VERSION 5.8 ;
BUSBITCHARS "[]" ;
DIVIDERCHAR "/" ;
UNITS
    DATABASE MICRONS 1000 ;
END UNITS

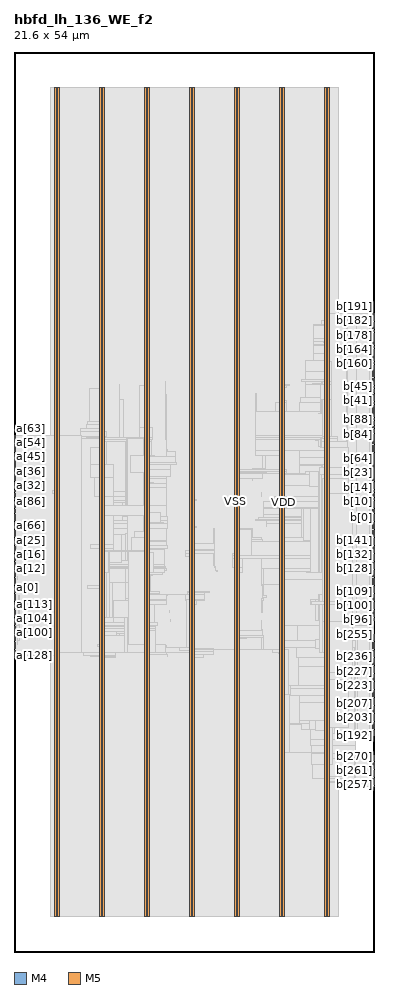
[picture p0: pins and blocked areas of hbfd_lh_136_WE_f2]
MACRO hbfd_lh_136_WE_f2
  FOREIGN hbfd_lh_136_WE_f2 0 0 ;
  CLASS BLOCK ;
  SIZE 21.6 BY 54 ;
  PIN a[0]
    DIRECTION INPUT ;
    USE SIGNAL ;
    PORT
      LAYER M4 ;
        RECT  0 21.84 0.084 21.864 ;
    END
  END a[0]
  PIN a[100]
    DIRECTION INPUT ;
    USE SIGNAL ;
    PORT
      LAYER M4 ;
        RECT  0 19.152 0.084 19.176 ;
    END
  END a[100]
  PIN a[101]
    DIRECTION INPUT ;
    USE SIGNAL ;
    PORT
      LAYER M4 ;
        RECT  0 19.248 0.084 19.272 ;
    END
  END a[101]
  PIN a[102]
    DIRECTION INPUT ;
    USE SIGNAL ;
    PORT
      LAYER M4 ;
        RECT  0 19.344 0.084 19.368 ;
    END
  END a[102]
  PIN a[103]
    DIRECTION INPUT ;
    USE SIGNAL ;
    PORT
      LAYER M4 ;
        RECT  0 19.44 0.084 19.464 ;
    END
  END a[103]
  PIN a[104]
    DIRECTION INPUT ;
    USE SIGNAL ;
    PORT
      LAYER M4 ;
        RECT  0 19.536 0.084 19.56 ;
    END
  END a[104]
  PIN a[105]
    DIRECTION INPUT ;
    USE SIGNAL ;
    PORT
      LAYER M4 ;
        RECT  0 19.632 0.084 19.656 ;
    END
  END a[105]
  PIN a[106]
    DIRECTION INPUT ;
    USE SIGNAL ;
    PORT
      LAYER M4 ;
        RECT  0 19.728 0.084 19.752 ;
    END
  END a[106]
  PIN a[107]
    DIRECTION INPUT ;
    USE SIGNAL ;
    PORT
      LAYER M4 ;
        RECT  0 19.824 0.084 19.848 ;
    END
  END a[107]
  PIN a[108]
    DIRECTION INPUT ;
    USE SIGNAL ;
    PORT
      LAYER M4 ;
        RECT  0 19.92 0.084 19.944 ;
    END
  END a[108]
  PIN a[109]
    DIRECTION INPUT ;
    USE SIGNAL ;
    PORT
      LAYER M4 ;
        RECT  0 20.016 0.084 20.04 ;
    END
  END a[109]
  PIN a[10]
    DIRECTION INPUT ;
    USE SIGNAL ;
    PORT
      LAYER M4 ;
        RECT  0 22.8 0.084 22.824 ;
    END
  END a[10]
  PIN a[110]
    DIRECTION INPUT ;
    USE SIGNAL ;
    PORT
      LAYER M4 ;
        RECT  0 20.112 0.084 20.136 ;
    END
  END a[110]
  PIN a[111]
    DIRECTION INPUT ;
    USE SIGNAL ;
    PORT
      LAYER M4 ;
        RECT  0 20.208 0.084 20.232 ;
    END
  END a[111]
  PIN a[112]
    DIRECTION INPUT ;
    USE SIGNAL ;
    PORT
      LAYER M4 ;
        RECT  0 20.304 0.084 20.328 ;
    END
  END a[112]
  PIN a[113]
    DIRECTION INPUT ;
    USE SIGNAL ;
    PORT
      LAYER M4 ;
        RECT  0 20.4 0.084 20.424 ;
    END
  END a[113]
  PIN a[114]
    DIRECTION INPUT ;
    USE SIGNAL ;
    PORT
      LAYER M4 ;
        RECT  0 20.496 0.084 20.52 ;
    END
  END a[114]
  PIN a[115]
    DIRECTION INPUT ;
    USE SIGNAL ;
    PORT
      LAYER M4 ;
        RECT  0 20.592 0.084 20.616 ;
    END
  END a[115]
  PIN a[116]
    DIRECTION INPUT ;
    USE SIGNAL ;
    PORT
      LAYER M4 ;
        RECT  0 20.688 0.084 20.712 ;
    END
  END a[116]
  PIN a[117]
    DIRECTION INPUT ;
    USE SIGNAL ;
    PORT
      LAYER M4 ;
        RECT  0 20.784 0.084 20.808 ;
    END
  END a[117]
  PIN a[118]
    DIRECTION INPUT ;
    USE SIGNAL ;
    PORT
      LAYER M4 ;
        RECT  0 20.88 0.084 20.904 ;
    END
  END a[118]
  PIN a[119]
    DIRECTION INPUT ;
    USE SIGNAL ;
    PORT
      LAYER M4 ;
        RECT  0 20.976 0.084 21 ;
    END
  END a[119]
  PIN a[11]
    DIRECTION INPUT ;
    USE SIGNAL ;
    PORT
      LAYER M4 ;
        RECT  0 22.896 0.084 22.92 ;
    END
  END a[11]
  PIN a[120]
    DIRECTION INPUT ;
    USE SIGNAL ;
    PORT
      LAYER M4 ;
        RECT  0 21.072 0.084 21.096 ;
    END
  END a[120]
  PIN a[121]
    DIRECTION INPUT ;
    USE SIGNAL ;
    PORT
      LAYER M4 ;
        RECT  0 21.168 0.084 21.192 ;
    END
  END a[121]
  PIN a[122]
    DIRECTION INPUT ;
    USE SIGNAL ;
    PORT
      LAYER M4 ;
        RECT  0 21.264 0.084 21.288 ;
    END
  END a[122]
  PIN a[123]
    DIRECTION INPUT ;
    USE SIGNAL ;
    PORT
      LAYER M4 ;
        RECT  0 21.36 0.084 21.384 ;
    END
  END a[123]
  PIN a[124]
    DIRECTION INPUT ;
    USE SIGNAL ;
    PORT
      LAYER M4 ;
        RECT  0 21.456 0.084 21.48 ;
    END
  END a[124]
  PIN a[125]
    DIRECTION INPUT ;
    USE SIGNAL ;
    PORT
      LAYER M4 ;
        RECT  0 21.552 0.084 21.576 ;
    END
  END a[125]
  PIN a[126]
    DIRECTION INPUT ;
    USE SIGNAL ;
    PORT
      LAYER M4 ;
        RECT  0 21.648 0.084 21.672 ;
    END
  END a[126]
  PIN a[127]
    DIRECTION INPUT ;
    USE SIGNAL ;
    PORT
      LAYER M4 ;
        RECT  0 21.744 0.084 21.768 ;
    END
  END a[127]
  PIN a[128]
    DIRECTION INPUT ;
    USE SIGNAL ;
    PORT
      LAYER M4 ;
        RECT  0 17.808 0.084 17.832 ;
    END
  END a[128]
  PIN a[129]
    DIRECTION INPUT ;
    USE SIGNAL ;
    PORT
      LAYER M4 ;
        RECT  0 17.904 0.084 17.928 ;
    END
  END a[129]
  PIN a[12]
    DIRECTION INPUT ;
    USE SIGNAL ;
    PORT
      LAYER M4 ;
        RECT  0 22.992 0.084 23.016 ;
    END
  END a[12]
  PIN a[130]
    DIRECTION INPUT ;
    USE SIGNAL ;
    PORT
      LAYER M4 ;
        RECT  0 18 0.084 18.024 ;
    END
  END a[130]
  PIN a[131]
    DIRECTION INPUT ;
    USE SIGNAL ;
    PORT
      LAYER M4 ;
        RECT  0 18.096 0.084 18.12 ;
    END
  END a[131]
  PIN a[132]
    DIRECTION INPUT ;
    USE SIGNAL ;
    PORT
      LAYER M4 ;
        RECT  0 18.192 0.084 18.216 ;
    END
  END a[132]
  PIN a[133]
    DIRECTION INPUT ;
    USE SIGNAL ;
    PORT
      LAYER M4 ;
        RECT  0 18.288 0.084 18.312 ;
    END
  END a[133]
  PIN a[134]
    DIRECTION INPUT ;
    USE SIGNAL ;
    PORT
      LAYER M4 ;
        RECT  0 18.384 0.084 18.408 ;
    END
  END a[134]
  PIN a[135]
    DIRECTION INPUT ;
    USE SIGNAL ;
    PORT
      LAYER M4 ;
        RECT  0 18.48 0.084 18.504 ;
    END
  END a[135]
  PIN a[13]
    DIRECTION INPUT ;
    USE SIGNAL ;
    PORT
      LAYER M4 ;
        RECT  0 23.088 0.084 23.112 ;
    END
  END a[13]
  PIN a[14]
    DIRECTION INPUT ;
    USE SIGNAL ;
    PORT
      LAYER M4 ;
        RECT  0 23.184 0.084 23.208 ;
    END
  END a[14]
  PIN a[15]
    DIRECTION INPUT ;
    USE SIGNAL ;
    PORT
      LAYER M4 ;
        RECT  0 23.28 0.084 23.304 ;
    END
  END a[15]
  PIN a[16]
    DIRECTION INPUT ;
    USE SIGNAL ;
    PORT
      LAYER M4 ;
        RECT  0 23.376 0.084 23.4 ;
    END
  END a[16]
  PIN a[17]
    DIRECTION INPUT ;
    USE SIGNAL ;
    PORT
      LAYER M4 ;
        RECT  0 23.472 0.084 23.496 ;
    END
  END a[17]
  PIN a[18]
    DIRECTION INPUT ;
    USE SIGNAL ;
    PORT
      LAYER M4 ;
        RECT  0 23.568 0.084 23.592 ;
    END
  END a[18]
  PIN a[19]
    DIRECTION INPUT ;
    USE SIGNAL ;
    PORT
      LAYER M4 ;
        RECT  0 23.664 0.084 23.688 ;
    END
  END a[19]
  PIN a[1]
    DIRECTION INPUT ;
    USE SIGNAL ;
    PORT
      LAYER M4 ;
        RECT  0 21.936 0.084 21.96 ;
    END
  END a[1]
  PIN a[20]
    DIRECTION INPUT ;
    USE SIGNAL ;
    PORT
      LAYER M4 ;
        RECT  0 23.76 0.084 23.784 ;
    END
  END a[20]
  PIN a[21]
    DIRECTION INPUT ;
    USE SIGNAL ;
    PORT
      LAYER M4 ;
        RECT  0 23.856 0.084 23.88 ;
    END
  END a[21]
  PIN a[22]
    DIRECTION INPUT ;
    USE SIGNAL ;
    PORT
      LAYER M4 ;
        RECT  0 23.952 0.084 23.976 ;
    END
  END a[22]
  PIN a[23]
    DIRECTION INPUT ;
    USE SIGNAL ;
    PORT
      LAYER M4 ;
        RECT  0 24.048 0.084 24.072 ;
    END
  END a[23]
  PIN a[24]
    DIRECTION INPUT ;
    USE SIGNAL ;
    PORT
      LAYER M4 ;
        RECT  0 24.144 0.084 24.168 ;
    END
  END a[24]
  PIN a[25]
    DIRECTION INPUT ;
    USE SIGNAL ;
    PORT
      LAYER M4 ;
        RECT  0 24.24 0.084 24.264 ;
    END
  END a[25]
  PIN a[26]
    DIRECTION INPUT ;
    USE SIGNAL ;
    PORT
      LAYER M4 ;
        RECT  0 24.336 0.084 24.36 ;
    END
  END a[26]
  PIN a[27]
    DIRECTION INPUT ;
    USE SIGNAL ;
    PORT
      LAYER M4 ;
        RECT  0 24.432 0.084 24.456 ;
    END
  END a[27]
  PIN a[28]
    DIRECTION INPUT ;
    USE SIGNAL ;
    PORT
      LAYER M4 ;
        RECT  0 24.528 0.084 24.552 ;
    END
  END a[28]
  PIN a[29]
    DIRECTION INPUT ;
    USE SIGNAL ;
    PORT
      LAYER M4 ;
        RECT  0 24.624 0.084 24.648 ;
    END
  END a[29]
  PIN a[2]
    DIRECTION INPUT ;
    USE SIGNAL ;
    PORT
      LAYER M4 ;
        RECT  0 22.032 0.084 22.056 ;
    END
  END a[2]
  PIN a[30]
    DIRECTION INPUT ;
    USE SIGNAL ;
    PORT
      LAYER M4 ;
        RECT  0 24.72 0.084 24.744 ;
    END
  END a[30]
  PIN a[31]
    DIRECTION INPUT ;
    USE SIGNAL ;
    PORT
      LAYER M4 ;
        RECT  0 24.816 0.084 24.84 ;
    END
  END a[31]
  PIN a[32]
    DIRECTION INPUT ;
    USE SIGNAL ;
    PORT
      LAYER M4 ;
        RECT  0 27.984 0.084 28.008 ;
    END
  END a[32]
  PIN a[33]
    DIRECTION INPUT ;
    USE SIGNAL ;
    PORT
      LAYER M4 ;
        RECT  0 28.08 0.084 28.104 ;
    END
  END a[33]
  PIN a[34]
    DIRECTION INPUT ;
    USE SIGNAL ;
    PORT
      LAYER M4 ;
        RECT  0 28.176 0.084 28.2 ;
    END
  END a[34]
  PIN a[35]
    DIRECTION INPUT ;
    USE SIGNAL ;
    PORT
      LAYER M4 ;
        RECT  0 28.272 0.084 28.296 ;
    END
  END a[35]
  PIN a[36]
    DIRECTION INPUT ;
    USE SIGNAL ;
    PORT
      LAYER M4 ;
        RECT  0 28.368 0.084 28.392 ;
    END
  END a[36]
  PIN a[37]
    DIRECTION INPUT ;
    USE SIGNAL ;
    PORT
      LAYER M4 ;
        RECT  0 28.464 0.084 28.488 ;
    END
  END a[37]
  PIN a[38]
    DIRECTION INPUT ;
    USE SIGNAL ;
    PORT
      LAYER M4 ;
        RECT  0 28.56 0.084 28.584 ;
    END
  END a[38]
  PIN a[39]
    DIRECTION INPUT ;
    USE SIGNAL ;
    PORT
      LAYER M4 ;
        RECT  0 28.656 0.084 28.68 ;
    END
  END a[39]
  PIN a[3]
    DIRECTION INPUT ;
    USE SIGNAL ;
    PORT
      LAYER M4 ;
        RECT  0 22.128 0.084 22.152 ;
    END
  END a[3]
  PIN a[40]
    DIRECTION INPUT ;
    USE SIGNAL ;
    PORT
      LAYER M4 ;
        RECT  0 28.752 0.084 28.776 ;
    END
  END a[40]
  PIN a[41]
    DIRECTION INPUT ;
    USE SIGNAL ;
    PORT
      LAYER M4 ;
        RECT  0 28.848 0.084 28.872 ;
    END
  END a[41]
  PIN a[42]
    DIRECTION INPUT ;
    USE SIGNAL ;
    PORT
      LAYER M4 ;
        RECT  0 28.944 0.084 28.968 ;
    END
  END a[42]
  PIN a[43]
    DIRECTION INPUT ;
    USE SIGNAL ;
    PORT
      LAYER M4 ;
        RECT  0 29.04 0.084 29.064 ;
    END
  END a[43]
  PIN a[44]
    DIRECTION INPUT ;
    USE SIGNAL ;
    PORT
      LAYER M4 ;
        RECT  0 29.136 0.084 29.16 ;
    END
  END a[44]
  PIN a[45]
    DIRECTION INPUT ;
    USE SIGNAL ;
    PORT
      LAYER M4 ;
        RECT  0 29.232 0.084 29.256 ;
    END
  END a[45]
  PIN a[46]
    DIRECTION INPUT ;
    USE SIGNAL ;
    PORT
      LAYER M4 ;
        RECT  0 29.328 0.084 29.352 ;
    END
  END a[46]
  PIN a[47]
    DIRECTION INPUT ;
    USE SIGNAL ;
    PORT
      LAYER M4 ;
        RECT  0 29.424 0.084 29.448 ;
    END
  END a[47]
  PIN a[48]
    DIRECTION INPUT ;
    USE SIGNAL ;
    PORT
      LAYER M4 ;
        RECT  0 29.52 0.084 29.544 ;
    END
  END a[48]
  PIN a[49]
    DIRECTION INPUT ;
    USE SIGNAL ;
    PORT
      LAYER M4 ;
        RECT  0 29.616 0.084 29.64 ;
    END
  END a[49]
  PIN a[4]
    DIRECTION INPUT ;
    USE SIGNAL ;
    PORT
      LAYER M4 ;
        RECT  0 22.224 0.084 22.248 ;
    END
  END a[4]
  PIN a[50]
    DIRECTION INPUT ;
    USE SIGNAL ;
    PORT
      LAYER M4 ;
        RECT  0 29.712 0.084 29.736 ;
    END
  END a[50]
  PIN a[51]
    DIRECTION INPUT ;
    USE SIGNAL ;
    PORT
      LAYER M4 ;
        RECT  0 29.808 0.084 29.832 ;
    END
  END a[51]
  PIN a[52]
    DIRECTION INPUT ;
    USE SIGNAL ;
    PORT
      LAYER M4 ;
        RECT  0 29.904 0.084 29.928 ;
    END
  END a[52]
  PIN a[53]
    DIRECTION INPUT ;
    USE SIGNAL ;
    PORT
      LAYER M4 ;
        RECT  0 30 0.084 30.024 ;
    END
  END a[53]
  PIN a[54]
    DIRECTION INPUT ;
    USE SIGNAL ;
    PORT
      LAYER M4 ;
        RECT  0 30.096 0.084 30.12 ;
    END
  END a[54]
  PIN a[55]
    DIRECTION INPUT ;
    USE SIGNAL ;
    PORT
      LAYER M4 ;
        RECT  0 30.192 0.084 30.216 ;
    END
  END a[55]
  PIN a[56]
    DIRECTION INPUT ;
    USE SIGNAL ;
    PORT
      LAYER M4 ;
        RECT  0 30.288 0.084 30.312 ;
    END
  END a[56]
  PIN a[57]
    DIRECTION INPUT ;
    USE SIGNAL ;
    PORT
      LAYER M4 ;
        RECT  0 30.384 0.084 30.408 ;
    END
  END a[57]
  PIN a[58]
    DIRECTION INPUT ;
    USE SIGNAL ;
    PORT
      LAYER M4 ;
        RECT  0 30.48 0.084 30.504 ;
    END
  END a[58]
  PIN a[59]
    DIRECTION INPUT ;
    USE SIGNAL ;
    PORT
      LAYER M4 ;
        RECT  0 30.576 0.084 30.6 ;
    END
  END a[59]
  PIN a[5]
    DIRECTION INPUT ;
    USE SIGNAL ;
    PORT
      LAYER M4 ;
        RECT  0 22.32 0.084 22.344 ;
    END
  END a[5]
  PIN a[60]
    DIRECTION INPUT ;
    USE SIGNAL ;
    PORT
      LAYER M4 ;
        RECT  0 30.672 0.084 30.696 ;
    END
  END a[60]
  PIN a[61]
    DIRECTION INPUT ;
    USE SIGNAL ;
    PORT
      LAYER M4 ;
        RECT  0 30.768 0.084 30.792 ;
    END
  END a[61]
  PIN a[62]
    DIRECTION INPUT ;
    USE SIGNAL ;
    PORT
      LAYER M4 ;
        RECT  0 30.864 0.084 30.888 ;
    END
  END a[62]
  PIN a[63]
    DIRECTION INPUT ;
    USE SIGNAL ;
    PORT
      LAYER M4 ;
        RECT  0 30.96 0.084 30.984 ;
    END
  END a[63]
  PIN a[64]
    DIRECTION INPUT ;
    USE SIGNAL ;
    PORT
      LAYER M4 ;
        RECT  0 24.912 0.084 24.936 ;
    END
  END a[64]
  PIN a[65]
    DIRECTION INPUT ;
    USE SIGNAL ;
    PORT
      LAYER M4 ;
        RECT  0 25.008 0.084 25.032 ;
    END
  END a[65]
  PIN a[66]
    DIRECTION INPUT ;
    USE SIGNAL ;
    PORT
      LAYER M4 ;
        RECT  0 25.104 0.084 25.128 ;
    END
  END a[66]
  PIN a[67]
    DIRECTION INPUT ;
    USE SIGNAL ;
    PORT
      LAYER M4 ;
        RECT  0 25.2 0.084 25.224 ;
    END
  END a[67]
  PIN a[68]
    DIRECTION INPUT ;
    USE SIGNAL ;
    PORT
      LAYER M4 ;
        RECT  0 25.296 0.084 25.32 ;
    END
  END a[68]
  PIN a[69]
    DIRECTION INPUT ;
    USE SIGNAL ;
    PORT
      LAYER M4 ;
        RECT  0 25.392 0.084 25.416 ;
    END
  END a[69]
  PIN a[6]
    DIRECTION INPUT ;
    USE SIGNAL ;
    PORT
      LAYER M4 ;
        RECT  0 22.416 0.084 22.44 ;
    END
  END a[6]
  PIN a[70]
    DIRECTION INPUT ;
    USE SIGNAL ;
    PORT
      LAYER M4 ;
        RECT  0 25.488 0.084 25.512 ;
    END
  END a[70]
  PIN a[71]
    DIRECTION INPUT ;
    USE SIGNAL ;
    PORT
      LAYER M4 ;
        RECT  0 25.584 0.084 25.608 ;
    END
  END a[71]
  PIN a[72]
    DIRECTION INPUT ;
    USE SIGNAL ;
    PORT
      LAYER M4 ;
        RECT  0 25.68 0.084 25.704 ;
    END
  END a[72]
  PIN a[73]
    DIRECTION INPUT ;
    USE SIGNAL ;
    PORT
      LAYER M4 ;
        RECT  0 25.776 0.084 25.8 ;
    END
  END a[73]
  PIN a[74]
    DIRECTION INPUT ;
    USE SIGNAL ;
    PORT
      LAYER M4 ;
        RECT  0 25.872 0.084 25.896 ;
    END
  END a[74]
  PIN a[75]
    DIRECTION INPUT ;
    USE SIGNAL ;
    PORT
      LAYER M4 ;
        RECT  0 25.968 0.084 25.992 ;
    END
  END a[75]
  PIN a[76]
    DIRECTION INPUT ;
    USE SIGNAL ;
    PORT
      LAYER M4 ;
        RECT  0 26.064 0.084 26.088 ;
    END
  END a[76]
  PIN a[77]
    DIRECTION INPUT ;
    USE SIGNAL ;
    PORT
      LAYER M4 ;
        RECT  0 26.16 0.084 26.184 ;
    END
  END a[77]
  PIN a[78]
    DIRECTION INPUT ;
    USE SIGNAL ;
    PORT
      LAYER M4 ;
        RECT  0 26.256 0.084 26.28 ;
    END
  END a[78]
  PIN a[79]
    DIRECTION INPUT ;
    USE SIGNAL ;
    PORT
      LAYER M4 ;
        RECT  0 26.352 0.084 26.376 ;
    END
  END a[79]
  PIN a[7]
    DIRECTION INPUT ;
    USE SIGNAL ;
    PORT
      LAYER M4 ;
        RECT  0 22.512 0.084 22.536 ;
    END
  END a[7]
  PIN a[80]
    DIRECTION INPUT ;
    USE SIGNAL ;
    PORT
      LAYER M4 ;
        RECT  0 26.448 0.084 26.472 ;
    END
  END a[80]
  PIN a[81]
    DIRECTION INPUT ;
    USE SIGNAL ;
    PORT
      LAYER M4 ;
        RECT  0 26.544 0.084 26.568 ;
    END
  END a[81]
  PIN a[82]
    DIRECTION INPUT ;
    USE SIGNAL ;
    PORT
      LAYER M4 ;
        RECT  0 26.64 0.084 26.664 ;
    END
  END a[82]
  PIN a[83]
    DIRECTION INPUT ;
    USE SIGNAL ;
    PORT
      LAYER M4 ;
        RECT  0 26.736 0.084 26.76 ;
    END
  END a[83]
  PIN a[84]
    DIRECTION INPUT ;
    USE SIGNAL ;
    PORT
      LAYER M4 ;
        RECT  0 26.832 0.084 26.856 ;
    END
  END a[84]
  PIN a[85]
    DIRECTION INPUT ;
    USE SIGNAL ;
    PORT
      LAYER M4 ;
        RECT  0 26.928 0.084 26.952 ;
    END
  END a[85]
  PIN a[86]
    DIRECTION INPUT ;
    USE SIGNAL ;
    PORT
      LAYER M4 ;
        RECT  0 27.024 0.084 27.048 ;
    END
  END a[86]
  PIN a[87]
    DIRECTION INPUT ;
    USE SIGNAL ;
    PORT
      LAYER M4 ;
        RECT  0 27.12 0.084 27.144 ;
    END
  END a[87]
  PIN a[88]
    DIRECTION INPUT ;
    USE SIGNAL ;
    PORT
      LAYER M4 ;
        RECT  0 27.216 0.084 27.24 ;
    END
  END a[88]
  PIN a[89]
    DIRECTION INPUT ;
    USE SIGNAL ;
    PORT
      LAYER M4 ;
        RECT  0 27.312 0.084 27.336 ;
    END
  END a[89]
  PIN a[8]
    DIRECTION INPUT ;
    USE SIGNAL ;
    PORT
      LAYER M4 ;
        RECT  0 22.608 0.084 22.632 ;
    END
  END a[8]
  PIN a[90]
    DIRECTION INPUT ;
    USE SIGNAL ;
    PORT
      LAYER M4 ;
        RECT  0 27.408 0.084 27.432 ;
    END
  END a[90]
  PIN a[91]
    DIRECTION INPUT ;
    USE SIGNAL ;
    PORT
      LAYER M4 ;
        RECT  0 27.504 0.084 27.528 ;
    END
  END a[91]
  PIN a[92]
    DIRECTION INPUT ;
    USE SIGNAL ;
    PORT
      LAYER M4 ;
        RECT  0 27.6 0.084 27.624 ;
    END
  END a[92]
  PIN a[93]
    DIRECTION INPUT ;
    USE SIGNAL ;
    PORT
      LAYER M4 ;
        RECT  0 27.696 0.084 27.72 ;
    END
  END a[93]
  PIN a[94]
    DIRECTION INPUT ;
    USE SIGNAL ;
    PORT
      LAYER M4 ;
        RECT  0 27.792 0.084 27.816 ;
    END
  END a[94]
  PIN a[95]
    DIRECTION INPUT ;
    USE SIGNAL ;
    PORT
      LAYER M4 ;
        RECT  0 27.888 0.084 27.912 ;
    END
  END a[95]
  PIN a[96]
    DIRECTION INPUT ;
    USE SIGNAL ;
    PORT
      LAYER M4 ;
        RECT  0 18.768 0.084 18.792 ;
    END
  END a[96]
  PIN a[97]
    DIRECTION INPUT ;
    USE SIGNAL ;
    PORT
      LAYER M4 ;
        RECT  0 18.864 0.084 18.888 ;
    END
  END a[97]
  PIN a[98]
    DIRECTION INPUT ;
    USE SIGNAL ;
    PORT
      LAYER M4 ;
        RECT  0 18.96 0.084 18.984 ;
    END
  END a[98]
  PIN a[99]
    DIRECTION INPUT ;
    USE SIGNAL ;
    PORT
      LAYER M4 ;
        RECT  0 19.056 0.084 19.08 ;
    END
  END a[99]
  PIN a[9]
    DIRECTION INPUT ;
    USE SIGNAL ;
    PORT
      LAYER M4 ;
        RECT  0 22.704 0.084 22.728 ;
    END
  END a[9]
  PIN b[0]
    DIRECTION OUTPUT ;
    USE SIGNAL ;
    PORT
      LAYER M4 ;
        RECT  21.516 26.064 21.6 26.088 ;
    END
  END b[0]
  PIN b[100]
    DIRECTION OUTPUT ;
    USE SIGNAL ;
    PORT
      LAYER M4 ;
        RECT  21.516 20.304 21.6 20.328 ;
    END
  END b[100]
  PIN b[101]
    DIRECTION OUTPUT ;
    USE SIGNAL ;
    PORT
      LAYER M4 ;
        RECT  21.516 20.4 21.6 20.424 ;
    END
  END b[101]
  PIN b[102]
    DIRECTION OUTPUT ;
    USE SIGNAL ;
    PORT
      LAYER M4 ;
        RECT  21.516 20.496 21.6 20.52 ;
    END
  END b[102]
  PIN b[103]
    DIRECTION OUTPUT ;
    USE SIGNAL ;
    PORT
      LAYER M4 ;
        RECT  21.516 20.592 21.6 20.616 ;
    END
  END b[103]
  PIN b[104]
    DIRECTION OUTPUT ;
    USE SIGNAL ;
    PORT
      LAYER M4 ;
        RECT  21.516 20.688 21.6 20.712 ;
    END
  END b[104]
  PIN b[105]
    DIRECTION OUTPUT ;
    USE SIGNAL ;
    PORT
      LAYER M4 ;
        RECT  21.516 20.784 21.6 20.808 ;
    END
  END b[105]
  PIN b[106]
    DIRECTION OUTPUT ;
    USE SIGNAL ;
    PORT
      LAYER M4 ;
        RECT  21.516 20.88 21.6 20.904 ;
    END
  END b[106]
  PIN b[107]
    DIRECTION OUTPUT ;
    USE SIGNAL ;
    PORT
      LAYER M4 ;
        RECT  21.516 20.976 21.6 21 ;
    END
  END b[107]
  PIN b[108]
    DIRECTION OUTPUT ;
    USE SIGNAL ;
    PORT
      LAYER M4 ;
        RECT  21.516 21.072 21.6 21.096 ;
    END
  END b[108]
  PIN b[109]
    DIRECTION OUTPUT ;
    USE SIGNAL ;
    PORT
      LAYER M4 ;
        RECT  21.516 21.168 21.6 21.192 ;
    END
  END b[109]
  PIN b[10]
    DIRECTION OUTPUT ;
    USE SIGNAL ;
    PORT
      LAYER M4 ;
        RECT  21.516 27.024 21.6 27.048 ;
    END
  END b[10]
  PIN b[110]
    DIRECTION OUTPUT ;
    USE SIGNAL ;
    PORT
      LAYER M4 ;
        RECT  21.516 21.264 21.6 21.288 ;
    END
  END b[110]
  PIN b[111]
    DIRECTION OUTPUT ;
    USE SIGNAL ;
    PORT
      LAYER M4 ;
        RECT  21.516 21.36 21.6 21.384 ;
    END
  END b[111]
  PIN b[112]
    DIRECTION OUTPUT ;
    USE SIGNAL ;
    PORT
      LAYER M4 ;
        RECT  21.516 21.456 21.6 21.48 ;
    END
  END b[112]
  PIN b[113]
    DIRECTION OUTPUT ;
    USE SIGNAL ;
    PORT
      LAYER M4 ;
        RECT  21.516 21.552 21.6 21.576 ;
    END
  END b[113]
  PIN b[114]
    DIRECTION OUTPUT ;
    USE SIGNAL ;
    PORT
      LAYER M4 ;
        RECT  21.516 21.648 21.6 21.672 ;
    END
  END b[114]
  PIN b[115]
    DIRECTION OUTPUT ;
    USE SIGNAL ;
    PORT
      LAYER M4 ;
        RECT  21.516 21.744 21.6 21.768 ;
    END
  END b[115]
  PIN b[116]
    DIRECTION OUTPUT ;
    USE SIGNAL ;
    PORT
      LAYER M4 ;
        RECT  21.516 21.84 21.6 21.864 ;
    END
  END b[116]
  PIN b[117]
    DIRECTION OUTPUT ;
    USE SIGNAL ;
    PORT
      LAYER M4 ;
        RECT  21.516 21.936 21.6 21.96 ;
    END
  END b[117]
  PIN b[118]
    DIRECTION OUTPUT ;
    USE SIGNAL ;
    PORT
      LAYER M4 ;
        RECT  21.516 22.032 21.6 22.056 ;
    END
  END b[118]
  PIN b[119]
    DIRECTION OUTPUT ;
    USE SIGNAL ;
    PORT
      LAYER M4 ;
        RECT  21.516 22.128 21.6 22.152 ;
    END
  END b[119]
  PIN b[11]
    DIRECTION OUTPUT ;
    USE SIGNAL ;
    PORT
      LAYER M4 ;
        RECT  21.516 27.12 21.6 27.144 ;
    END
  END b[11]
  PIN b[120]
    DIRECTION OUTPUT ;
    USE SIGNAL ;
    PORT
      LAYER M4 ;
        RECT  21.516 22.224 21.6 22.248 ;
    END
  END b[120]
  PIN b[121]
    DIRECTION OUTPUT ;
    USE SIGNAL ;
    PORT
      LAYER M4 ;
        RECT  21.516 22.32 21.6 22.344 ;
    END
  END b[121]
  PIN b[122]
    DIRECTION OUTPUT ;
    USE SIGNAL ;
    PORT
      LAYER M4 ;
        RECT  21.516 22.416 21.6 22.44 ;
    END
  END b[122]
  PIN b[123]
    DIRECTION OUTPUT ;
    USE SIGNAL ;
    PORT
      LAYER M4 ;
        RECT  21.516 22.512 21.6 22.536 ;
    END
  END b[123]
  PIN b[124]
    DIRECTION OUTPUT ;
    USE SIGNAL ;
    PORT
      LAYER M4 ;
        RECT  21.516 22.608 21.6 22.632 ;
    END
  END b[124]
  PIN b[125]
    DIRECTION OUTPUT ;
    USE SIGNAL ;
    PORT
      LAYER M4 ;
        RECT  21.516 22.704 21.6 22.728 ;
    END
  END b[125]
  PIN b[126]
    DIRECTION OUTPUT ;
    USE SIGNAL ;
    PORT
      LAYER M4 ;
        RECT  21.516 22.8 21.6 22.824 ;
    END
  END b[126]
  PIN b[127]
    DIRECTION OUTPUT ;
    USE SIGNAL ;
    PORT
      LAYER M4 ;
        RECT  21.516 22.896 21.6 22.92 ;
    END
  END b[127]
  PIN b[128]
    DIRECTION OUTPUT ;
    USE SIGNAL ;
    PORT
      LAYER M4 ;
        RECT  21.516 22.992 21.6 23.016 ;
    END
  END b[128]
  PIN b[129]
    DIRECTION OUTPUT ;
    USE SIGNAL ;
    PORT
      LAYER M4 ;
        RECT  21.516 23.088 21.6 23.112 ;
    END
  END b[129]
  PIN b[12]
    DIRECTION OUTPUT ;
    USE SIGNAL ;
    PORT
      LAYER M4 ;
        RECT  21.516 27.216 21.6 27.24 ;
    END
  END b[12]
  PIN b[130]
    DIRECTION OUTPUT ;
    USE SIGNAL ;
    PORT
      LAYER M4 ;
        RECT  21.516 23.184 21.6 23.208 ;
    END
  END b[130]
  PIN b[131]
    DIRECTION OUTPUT ;
    USE SIGNAL ;
    PORT
      LAYER M4 ;
        RECT  21.516 23.28 21.6 23.304 ;
    END
  END b[131]
  PIN b[132]
    DIRECTION OUTPUT ;
    USE SIGNAL ;
    PORT
      LAYER M4 ;
        RECT  21.516 23.376 21.6 23.4 ;
    END
  END b[132]
  PIN b[133]
    DIRECTION OUTPUT ;
    USE SIGNAL ;
    PORT
      LAYER M4 ;
        RECT  21.516 23.472 21.6 23.496 ;
    END
  END b[133]
  PIN b[134]
    DIRECTION OUTPUT ;
    USE SIGNAL ;
    PORT
      LAYER M4 ;
        RECT  21.516 23.568 21.6 23.592 ;
    END
  END b[134]
  PIN b[135]
    DIRECTION OUTPUT ;
    USE SIGNAL ;
    PORT
      LAYER M4 ;
        RECT  21.516 23.664 21.6 23.688 ;
    END
  END b[135]
  PIN b[136]
    DIRECTION OUTPUT ;
    USE SIGNAL ;
    PORT
      LAYER M4 ;
        RECT  21.516 23.76 21.6 23.784 ;
    END
  END b[136]
  PIN b[137]
    DIRECTION OUTPUT ;
    USE SIGNAL ;
    PORT
      LAYER M4 ;
        RECT  21.516 23.856 21.6 23.88 ;
    END
  END b[137]
  PIN b[138]
    DIRECTION OUTPUT ;
    USE SIGNAL ;
    PORT
      LAYER M4 ;
        RECT  21.516 23.952 21.6 23.976 ;
    END
  END b[138]
  PIN b[139]
    DIRECTION OUTPUT ;
    USE SIGNAL ;
    PORT
      LAYER M4 ;
        RECT  21.516 24.048 21.6 24.072 ;
    END
  END b[139]
  PIN b[13]
    DIRECTION OUTPUT ;
    USE SIGNAL ;
    PORT
      LAYER M4 ;
        RECT  21.516 27.312 21.6 27.336 ;
    END
  END b[13]
  PIN b[140]
    DIRECTION OUTPUT ;
    USE SIGNAL ;
    PORT
      LAYER M4 ;
        RECT  21.516 24.144 21.6 24.168 ;
    END
  END b[140]
  PIN b[141]
    DIRECTION OUTPUT ;
    USE SIGNAL ;
    PORT
      LAYER M4 ;
        RECT  21.516 24.24 21.6 24.264 ;
    END
  END b[141]
  PIN b[142]
    DIRECTION OUTPUT ;
    USE SIGNAL ;
    PORT
      LAYER M4 ;
        RECT  21.516 24.336 21.6 24.36 ;
    END
  END b[142]
  PIN b[143]
    DIRECTION OUTPUT ;
    USE SIGNAL ;
    PORT
      LAYER M4 ;
        RECT  21.516 24.432 21.6 24.456 ;
    END
  END b[143]
  PIN b[144]
    DIRECTION OUTPUT ;
    USE SIGNAL ;
    PORT
      LAYER M4 ;
        RECT  21.516 24.528 21.6 24.552 ;
    END
  END b[144]
  PIN b[145]
    DIRECTION OUTPUT ;
    USE SIGNAL ;
    PORT
      LAYER M4 ;
        RECT  21.516 24.624 21.6 24.648 ;
    END
  END b[145]
  PIN b[146]
    DIRECTION OUTPUT ;
    USE SIGNAL ;
    PORT
      LAYER M4 ;
        RECT  21.516 24.72 21.6 24.744 ;
    END
  END b[146]
  PIN b[147]
    DIRECTION OUTPUT ;
    USE SIGNAL ;
    PORT
      LAYER M4 ;
        RECT  21.516 24.816 21.6 24.84 ;
    END
  END b[147]
  PIN b[148]
    DIRECTION OUTPUT ;
    USE SIGNAL ;
    PORT
      LAYER M4 ;
        RECT  21.516 24.912 21.6 24.936 ;
    END
  END b[148]
  PIN b[149]
    DIRECTION OUTPUT ;
    USE SIGNAL ;
    PORT
      LAYER M4 ;
        RECT  21.516 25.008 21.6 25.032 ;
    END
  END b[149]
  PIN b[14]
    DIRECTION OUTPUT ;
    USE SIGNAL ;
    PORT
      LAYER M4 ;
        RECT  21.516 27.408 21.6 27.432 ;
    END
  END b[14]
  PIN b[150]
    DIRECTION OUTPUT ;
    USE SIGNAL ;
    PORT
      LAYER M4 ;
        RECT  21.516 25.104 21.6 25.128 ;
    END
  END b[150]
  PIN b[151]
    DIRECTION OUTPUT ;
    USE SIGNAL ;
    PORT
      LAYER M4 ;
        RECT  21.516 25.2 21.6 25.224 ;
    END
  END b[151]
  PIN b[152]
    DIRECTION OUTPUT ;
    USE SIGNAL ;
    PORT
      LAYER M4 ;
        RECT  21.516 25.296 21.6 25.32 ;
    END
  END b[152]
  PIN b[153]
    DIRECTION OUTPUT ;
    USE SIGNAL ;
    PORT
      LAYER M4 ;
        RECT  21.516 25.392 21.6 25.416 ;
    END
  END b[153]
  PIN b[154]
    DIRECTION OUTPUT ;
    USE SIGNAL ;
    PORT
      LAYER M4 ;
        RECT  21.516 25.488 21.6 25.512 ;
    END
  END b[154]
  PIN b[155]
    DIRECTION OUTPUT ;
    USE SIGNAL ;
    PORT
      LAYER M4 ;
        RECT  21.516 25.584 21.6 25.608 ;
    END
  END b[155]
  PIN b[156]
    DIRECTION OUTPUT ;
    USE SIGNAL ;
    PORT
      LAYER M4 ;
        RECT  21.516 25.68 21.6 25.704 ;
    END
  END b[156]
  PIN b[157]
    DIRECTION OUTPUT ;
    USE SIGNAL ;
    PORT
      LAYER M4 ;
        RECT  21.516 25.776 21.6 25.8 ;
    END
  END b[157]
  PIN b[158]
    DIRECTION OUTPUT ;
    USE SIGNAL ;
    PORT
      LAYER M4 ;
        RECT  21.516 25.872 21.6 25.896 ;
    END
  END b[158]
  PIN b[159]
    DIRECTION OUTPUT ;
    USE SIGNAL ;
    PORT
      LAYER M4 ;
        RECT  21.516 25.968 21.6 25.992 ;
    END
  END b[159]
  PIN b[15]
    DIRECTION OUTPUT ;
    USE SIGNAL ;
    PORT
      LAYER M4 ;
        RECT  21.516 27.504 21.6 27.528 ;
    END
  END b[15]
  PIN b[160]
    DIRECTION OUTPUT ;
    USE SIGNAL ;
    PORT
      LAYER M4 ;
        RECT  21.516 35.28 21.6 35.304 ;
    END
  END b[160]
  PIN b[161]
    DIRECTION OUTPUT ;
    USE SIGNAL ;
    PORT
      LAYER M4 ;
        RECT  21.516 35.376 21.6 35.4 ;
    END
  END b[161]
  PIN b[162]
    DIRECTION OUTPUT ;
    USE SIGNAL ;
    PORT
      LAYER M4 ;
        RECT  21.516 35.472 21.6 35.496 ;
    END
  END b[162]
  PIN b[163]
    DIRECTION OUTPUT ;
    USE SIGNAL ;
    PORT
      LAYER M4 ;
        RECT  21.516 35.568 21.6 35.592 ;
    END
  END b[163]
  PIN b[164]
    DIRECTION OUTPUT ;
    USE SIGNAL ;
    PORT
      LAYER M4 ;
        RECT  21.516 35.664 21.6 35.688 ;
    END
  END b[164]
  PIN b[165]
    DIRECTION OUTPUT ;
    USE SIGNAL ;
    PORT
      LAYER M4 ;
        RECT  21.516 35.76 21.6 35.784 ;
    END
  END b[165]
  PIN b[166]
    DIRECTION OUTPUT ;
    USE SIGNAL ;
    PORT
      LAYER M4 ;
        RECT  21.516 35.856 21.6 35.88 ;
    END
  END b[166]
  PIN b[167]
    DIRECTION OUTPUT ;
    USE SIGNAL ;
    PORT
      LAYER M4 ;
        RECT  21.516 35.952 21.6 35.976 ;
    END
  END b[167]
  PIN b[168]
    DIRECTION OUTPUT ;
    USE SIGNAL ;
    PORT
      LAYER M4 ;
        RECT  21.516 36.048 21.6 36.072 ;
    END
  END b[168]
  PIN b[169]
    DIRECTION OUTPUT ;
    USE SIGNAL ;
    PORT
      LAYER M4 ;
        RECT  21.516 36.144 21.6 36.168 ;
    END
  END b[169]
  PIN b[16]
    DIRECTION OUTPUT ;
    USE SIGNAL ;
    PORT
      LAYER M4 ;
        RECT  21.516 27.6 21.6 27.624 ;
    END
  END b[16]
  PIN b[170]
    DIRECTION OUTPUT ;
    USE SIGNAL ;
    PORT
      LAYER M4 ;
        RECT  21.516 36.24 21.6 36.264 ;
    END
  END b[170]
  PIN b[171]
    DIRECTION OUTPUT ;
    USE SIGNAL ;
    PORT
      LAYER M4 ;
        RECT  21.516 36.336 21.6 36.36 ;
    END
  END b[171]
  PIN b[172]
    DIRECTION OUTPUT ;
    USE SIGNAL ;
    PORT
      LAYER M4 ;
        RECT  21.516 36.432 21.6 36.456 ;
    END
  END b[172]
  PIN b[173]
    DIRECTION OUTPUT ;
    USE SIGNAL ;
    PORT
      LAYER M4 ;
        RECT  21.516 36.528 21.6 36.552 ;
    END
  END b[173]
  PIN b[174]
    DIRECTION OUTPUT ;
    USE SIGNAL ;
    PORT
      LAYER M4 ;
        RECT  21.516 36.624 21.6 36.648 ;
    END
  END b[174]
  PIN b[175]
    DIRECTION OUTPUT ;
    USE SIGNAL ;
    PORT
      LAYER M4 ;
        RECT  21.516 36.72 21.6 36.744 ;
    END
  END b[175]
  PIN b[176]
    DIRECTION OUTPUT ;
    USE SIGNAL ;
    PORT
      LAYER M4 ;
        RECT  21.516 36.816 21.6 36.84 ;
    END
  END b[176]
  PIN b[177]
    DIRECTION OUTPUT ;
    USE SIGNAL ;
    PORT
      LAYER M4 ;
        RECT  21.516 36.912 21.6 36.936 ;
    END
  END b[177]
  PIN b[178]
    DIRECTION OUTPUT ;
    USE SIGNAL ;
    PORT
      LAYER M4 ;
        RECT  21.516 37.008 21.6 37.032 ;
    END
  END b[178]
  PIN b[179]
    DIRECTION OUTPUT ;
    USE SIGNAL ;
    PORT
      LAYER M4 ;
        RECT  21.516 37.104 21.6 37.128 ;
    END
  END b[179]
  PIN b[17]
    DIRECTION OUTPUT ;
    USE SIGNAL ;
    PORT
      LAYER M4 ;
        RECT  21.516 27.696 21.6 27.72 ;
    END
  END b[17]
  PIN b[180]
    DIRECTION OUTPUT ;
    USE SIGNAL ;
    PORT
      LAYER M4 ;
        RECT  21.516 37.2 21.6 37.224 ;
    END
  END b[180]
  PIN b[181]
    DIRECTION OUTPUT ;
    USE SIGNAL ;
    PORT
      LAYER M4 ;
        RECT  21.516 37.296 21.6 37.32 ;
    END
  END b[181]
  PIN b[182]
    DIRECTION OUTPUT ;
    USE SIGNAL ;
    PORT
      LAYER M4 ;
        RECT  21.516 37.392 21.6 37.416 ;
    END
  END b[182]
  PIN b[183]
    DIRECTION OUTPUT ;
    USE SIGNAL ;
    PORT
      LAYER M4 ;
        RECT  21.516 37.488 21.6 37.512 ;
    END
  END b[183]
  PIN b[184]
    DIRECTION OUTPUT ;
    USE SIGNAL ;
    PORT
      LAYER M4 ;
        RECT  21.516 37.584 21.6 37.608 ;
    END
  END b[184]
  PIN b[185]
    DIRECTION OUTPUT ;
    USE SIGNAL ;
    PORT
      LAYER M4 ;
        RECT  21.516 37.68 21.6 37.704 ;
    END
  END b[185]
  PIN b[186]
    DIRECTION OUTPUT ;
    USE SIGNAL ;
    PORT
      LAYER M4 ;
        RECT  21.516 37.776 21.6 37.8 ;
    END
  END b[186]
  PIN b[187]
    DIRECTION OUTPUT ;
    USE SIGNAL ;
    PORT
      LAYER M4 ;
        RECT  21.516 37.872 21.6 37.896 ;
    END
  END b[187]
  PIN b[188]
    DIRECTION OUTPUT ;
    USE SIGNAL ;
    PORT
      LAYER M4 ;
        RECT  21.516 37.968 21.6 37.992 ;
    END
  END b[188]
  PIN b[189]
    DIRECTION OUTPUT ;
    USE SIGNAL ;
    PORT
      LAYER M4 ;
        RECT  21.516 38.064 21.6 38.088 ;
    END
  END b[189]
  PIN b[18]
    DIRECTION OUTPUT ;
    USE SIGNAL ;
    PORT
      LAYER M4 ;
        RECT  21.516 27.792 21.6 27.816 ;
    END
  END b[18]
  PIN b[190]
    DIRECTION OUTPUT ;
    USE SIGNAL ;
    PORT
      LAYER M4 ;
        RECT  21.516 38.16 21.6 38.184 ;
    END
  END b[190]
  PIN b[191]
    DIRECTION OUTPUT ;
    USE SIGNAL ;
    PORT
      LAYER M4 ;
        RECT  21.516 38.256 21.6 38.28 ;
    END
  END b[191]
  PIN b[192]
    DIRECTION OUTPUT ;
    USE SIGNAL ;
    PORT
      LAYER M4 ;
        RECT  21.516 13.008 21.6 13.032 ;
    END
  END b[192]
  PIN b[193]
    DIRECTION OUTPUT ;
    USE SIGNAL ;
    PORT
      LAYER M4 ;
        RECT  21.516 13.104 21.6 13.128 ;
    END
  END b[193]
  PIN b[194]
    DIRECTION OUTPUT ;
    USE SIGNAL ;
    PORT
      LAYER M4 ;
        RECT  21.516 13.2 21.6 13.224 ;
    END
  END b[194]
  PIN b[195]
    DIRECTION OUTPUT ;
    USE SIGNAL ;
    PORT
      LAYER M4 ;
        RECT  21.516 13.296 21.6 13.32 ;
    END
  END b[195]
  PIN b[196]
    DIRECTION OUTPUT ;
    USE SIGNAL ;
    PORT
      LAYER M4 ;
        RECT  21.516 13.392 21.6 13.416 ;
    END
  END b[196]
  PIN b[197]
    DIRECTION OUTPUT ;
    USE SIGNAL ;
    PORT
      LAYER M4 ;
        RECT  21.516 13.488 21.6 13.512 ;
    END
  END b[197]
  PIN b[198]
    DIRECTION OUTPUT ;
    USE SIGNAL ;
    PORT
      LAYER M4 ;
        RECT  21.516 13.584 21.6 13.608 ;
    END
  END b[198]
  PIN b[199]
    DIRECTION OUTPUT ;
    USE SIGNAL ;
    PORT
      LAYER M4 ;
        RECT  21.516 13.68 21.6 13.704 ;
    END
  END b[199]
  PIN b[19]
    DIRECTION OUTPUT ;
    USE SIGNAL ;
    PORT
      LAYER M4 ;
        RECT  21.516 27.888 21.6 27.912 ;
    END
  END b[19]
  PIN b[1]
    DIRECTION OUTPUT ;
    USE SIGNAL ;
    PORT
      LAYER M4 ;
        RECT  21.516 26.16 21.6 26.184 ;
    END
  END b[1]
  PIN b[200]
    DIRECTION OUTPUT ;
    USE SIGNAL ;
    PORT
      LAYER M4 ;
        RECT  21.516 13.776 21.6 13.8 ;
    END
  END b[200]
  PIN b[201]
    DIRECTION OUTPUT ;
    USE SIGNAL ;
    PORT
      LAYER M4 ;
        RECT  21.516 13.872 21.6 13.896 ;
    END
  END b[201]
  PIN b[202]
    DIRECTION OUTPUT ;
    USE SIGNAL ;
    PORT
      LAYER M4 ;
        RECT  21.516 13.968 21.6 13.992 ;
    END
  END b[202]
  PIN b[203]
    DIRECTION OUTPUT ;
    USE SIGNAL ;
    PORT
      LAYER M4 ;
        RECT  21.516 14.064 21.6 14.088 ;
    END
  END b[203]
  PIN b[204]
    DIRECTION OUTPUT ;
    USE SIGNAL ;
    PORT
      LAYER M4 ;
        RECT  21.516 14.16 21.6 14.184 ;
    END
  END b[204]
  PIN b[205]
    DIRECTION OUTPUT ;
    USE SIGNAL ;
    PORT
      LAYER M4 ;
        RECT  21.516 14.256 21.6 14.28 ;
    END
  END b[205]
  PIN b[206]
    DIRECTION OUTPUT ;
    USE SIGNAL ;
    PORT
      LAYER M4 ;
        RECT  21.516 14.352 21.6 14.376 ;
    END
  END b[206]
  PIN b[207]
    DIRECTION OUTPUT ;
    USE SIGNAL ;
    PORT
      LAYER M4 ;
        RECT  21.516 14.448 21.6 14.472 ;
    END
  END b[207]
  PIN b[208]
    DIRECTION OUTPUT ;
    USE SIGNAL ;
    PORT
      LAYER M4 ;
        RECT  21.516 14.544 21.6 14.568 ;
    END
  END b[208]
  PIN b[209]
    DIRECTION OUTPUT ;
    USE SIGNAL ;
    PORT
      LAYER M4 ;
        RECT  21.516 14.64 21.6 14.664 ;
    END
  END b[209]
  PIN b[20]
    DIRECTION OUTPUT ;
    USE SIGNAL ;
    PORT
      LAYER M4 ;
        RECT  21.516 27.984 21.6 28.008 ;
    END
  END b[20]
  PIN b[210]
    DIRECTION OUTPUT ;
    USE SIGNAL ;
    PORT
      LAYER M4 ;
        RECT  21.516 14.736 21.6 14.76 ;
    END
  END b[210]
  PIN b[211]
    DIRECTION OUTPUT ;
    USE SIGNAL ;
    PORT
      LAYER M4 ;
        RECT  21.516 14.832 21.6 14.856 ;
    END
  END b[211]
  PIN b[212]
    DIRECTION OUTPUT ;
    USE SIGNAL ;
    PORT
      LAYER M4 ;
        RECT  21.516 14.928 21.6 14.952 ;
    END
  END b[212]
  PIN b[213]
    DIRECTION OUTPUT ;
    USE SIGNAL ;
    PORT
      LAYER M4 ;
        RECT  21.516 15.024 21.6 15.048 ;
    END
  END b[213]
  PIN b[214]
    DIRECTION OUTPUT ;
    USE SIGNAL ;
    PORT
      LAYER M4 ;
        RECT  21.516 15.12 21.6 15.144 ;
    END
  END b[214]
  PIN b[215]
    DIRECTION OUTPUT ;
    USE SIGNAL ;
    PORT
      LAYER M4 ;
        RECT  21.516 15.216 21.6 15.24 ;
    END
  END b[215]
  PIN b[216]
    DIRECTION OUTPUT ;
    USE SIGNAL ;
    PORT
      LAYER M4 ;
        RECT  21.516 15.312 21.6 15.336 ;
    END
  END b[216]
  PIN b[217]
    DIRECTION OUTPUT ;
    USE SIGNAL ;
    PORT
      LAYER M4 ;
        RECT  21.516 15.408 21.6 15.432 ;
    END
  END b[217]
  PIN b[218]
    DIRECTION OUTPUT ;
    USE SIGNAL ;
    PORT
      LAYER M4 ;
        RECT  21.516 15.504 21.6 15.528 ;
    END
  END b[218]
  PIN b[219]
    DIRECTION OUTPUT ;
    USE SIGNAL ;
    PORT
      LAYER M4 ;
        RECT  21.516 15.6 21.6 15.624 ;
    END
  END b[219]
  PIN b[21]
    DIRECTION OUTPUT ;
    USE SIGNAL ;
    PORT
      LAYER M4 ;
        RECT  21.516 28.08 21.6 28.104 ;
    END
  END b[21]
  PIN b[220]
    DIRECTION OUTPUT ;
    USE SIGNAL ;
    PORT
      LAYER M4 ;
        RECT  21.516 15.696 21.6 15.72 ;
    END
  END b[220]
  PIN b[221]
    DIRECTION OUTPUT ;
    USE SIGNAL ;
    PORT
      LAYER M4 ;
        RECT  21.516 15.792 21.6 15.816 ;
    END
  END b[221]
  PIN b[222]
    DIRECTION OUTPUT ;
    USE SIGNAL ;
    PORT
      LAYER M4 ;
        RECT  21.516 15.888 21.6 15.912 ;
    END
  END b[222]
  PIN b[223]
    DIRECTION OUTPUT ;
    USE SIGNAL ;
    PORT
      LAYER M4 ;
        RECT  21.516 15.984 21.6 16.008 ;
    END
  END b[223]
  PIN b[224]
    DIRECTION OUTPUT ;
    USE SIGNAL ;
    PORT
      LAYER M4 ;
        RECT  21.516 16.08 21.6 16.104 ;
    END
  END b[224]
  PIN b[225]
    DIRECTION OUTPUT ;
    USE SIGNAL ;
    PORT
      LAYER M4 ;
        RECT  21.516 16.176 21.6 16.2 ;
    END
  END b[225]
  PIN b[226]
    DIRECTION OUTPUT ;
    USE SIGNAL ;
    PORT
      LAYER M4 ;
        RECT  21.516 16.272 21.6 16.296 ;
    END
  END b[226]
  PIN b[227]
    DIRECTION OUTPUT ;
    USE SIGNAL ;
    PORT
      LAYER M4 ;
        RECT  21.516 16.368 21.6 16.392 ;
    END
  END b[227]
  PIN b[228]
    DIRECTION OUTPUT ;
    USE SIGNAL ;
    PORT
      LAYER M4 ;
        RECT  21.516 16.464 21.6 16.488 ;
    END
  END b[228]
  PIN b[229]
    DIRECTION OUTPUT ;
    USE SIGNAL ;
    PORT
      LAYER M4 ;
        RECT  21.516 16.56 21.6 16.584 ;
    END
  END b[229]
  PIN b[22]
    DIRECTION OUTPUT ;
    USE SIGNAL ;
    PORT
      LAYER M4 ;
        RECT  21.516 28.176 21.6 28.2 ;
    END
  END b[22]
  PIN b[230]
    DIRECTION OUTPUT ;
    USE SIGNAL ;
    PORT
      LAYER M4 ;
        RECT  21.516 16.656 21.6 16.68 ;
    END
  END b[230]
  PIN b[231]
    DIRECTION OUTPUT ;
    USE SIGNAL ;
    PORT
      LAYER M4 ;
        RECT  21.516 16.752 21.6 16.776 ;
    END
  END b[231]
  PIN b[232]
    DIRECTION OUTPUT ;
    USE SIGNAL ;
    PORT
      LAYER M4 ;
        RECT  21.516 16.848 21.6 16.872 ;
    END
  END b[232]
  PIN b[233]
    DIRECTION OUTPUT ;
    USE SIGNAL ;
    PORT
      LAYER M4 ;
        RECT  21.516 16.944 21.6 16.968 ;
    END
  END b[233]
  PIN b[234]
    DIRECTION OUTPUT ;
    USE SIGNAL ;
    PORT
      LAYER M4 ;
        RECT  21.516 17.04 21.6 17.064 ;
    END
  END b[234]
  PIN b[235]
    DIRECTION OUTPUT ;
    USE SIGNAL ;
    PORT
      LAYER M4 ;
        RECT  21.516 17.136 21.6 17.16 ;
    END
  END b[235]
  PIN b[236]
    DIRECTION OUTPUT ;
    USE SIGNAL ;
    PORT
      LAYER M4 ;
        RECT  21.516 17.232 21.6 17.256 ;
    END
  END b[236]
  PIN b[237]
    DIRECTION OUTPUT ;
    USE SIGNAL ;
    PORT
      LAYER M4 ;
        RECT  21.516 17.328 21.6 17.352 ;
    END
  END b[237]
  PIN b[238]
    DIRECTION OUTPUT ;
    USE SIGNAL ;
    PORT
      LAYER M4 ;
        RECT  21.516 17.424 21.6 17.448 ;
    END
  END b[238]
  PIN b[239]
    DIRECTION OUTPUT ;
    USE SIGNAL ;
    PORT
      LAYER M4 ;
        RECT  21.516 17.52 21.6 17.544 ;
    END
  END b[239]
  PIN b[23]
    DIRECTION OUTPUT ;
    USE SIGNAL ;
    PORT
      LAYER M4 ;
        RECT  21.516 28.272 21.6 28.296 ;
    END
  END b[23]
  PIN b[240]
    DIRECTION OUTPUT ;
    USE SIGNAL ;
    PORT
      LAYER M4 ;
        RECT  21.516 17.616 21.6 17.64 ;
    END
  END b[240]
  PIN b[241]
    DIRECTION OUTPUT ;
    USE SIGNAL ;
    PORT
      LAYER M4 ;
        RECT  21.516 17.712 21.6 17.736 ;
    END
  END b[241]
  PIN b[242]
    DIRECTION OUTPUT ;
    USE SIGNAL ;
    PORT
      LAYER M4 ;
        RECT  21.516 17.808 21.6 17.832 ;
    END
  END b[242]
  PIN b[243]
    DIRECTION OUTPUT ;
    USE SIGNAL ;
    PORT
      LAYER M4 ;
        RECT  21.516 17.904 21.6 17.928 ;
    END
  END b[243]
  PIN b[244]
    DIRECTION OUTPUT ;
    USE SIGNAL ;
    PORT
      LAYER M4 ;
        RECT  21.516 18 21.6 18.024 ;
    END
  END b[244]
  PIN b[245]
    DIRECTION OUTPUT ;
    USE SIGNAL ;
    PORT
      LAYER M4 ;
        RECT  21.516 18.096 21.6 18.12 ;
    END
  END b[245]
  PIN b[246]
    DIRECTION OUTPUT ;
    USE SIGNAL ;
    PORT
      LAYER M4 ;
        RECT  21.516 18.192 21.6 18.216 ;
    END
  END b[246]
  PIN b[247]
    DIRECTION OUTPUT ;
    USE SIGNAL ;
    PORT
      LAYER M4 ;
        RECT  21.516 18.288 21.6 18.312 ;
    END
  END b[247]
  PIN b[248]
    DIRECTION OUTPUT ;
    USE SIGNAL ;
    PORT
      LAYER M4 ;
        RECT  21.516 18.384 21.6 18.408 ;
    END
  END b[248]
  PIN b[249]
    DIRECTION OUTPUT ;
    USE SIGNAL ;
    PORT
      LAYER M4 ;
        RECT  21.516 18.48 21.6 18.504 ;
    END
  END b[249]
  PIN b[24]
    DIRECTION OUTPUT ;
    USE SIGNAL ;
    PORT
      LAYER M4 ;
        RECT  21.516 28.368 21.6 28.392 ;
    END
  END b[24]
  PIN b[250]
    DIRECTION OUTPUT ;
    USE SIGNAL ;
    PORT
      LAYER M4 ;
        RECT  21.516 18.576 21.6 18.6 ;
    END
  END b[250]
  PIN b[251]
    DIRECTION OUTPUT ;
    USE SIGNAL ;
    PORT
      LAYER M4 ;
        RECT  21.516 18.672 21.6 18.696 ;
    END
  END b[251]
  PIN b[252]
    DIRECTION OUTPUT ;
    USE SIGNAL ;
    PORT
      LAYER M4 ;
        RECT  21.516 18.768 21.6 18.792 ;
    END
  END b[252]
  PIN b[253]
    DIRECTION OUTPUT ;
    USE SIGNAL ;
    PORT
      LAYER M4 ;
        RECT  21.516 18.864 21.6 18.888 ;
    END
  END b[253]
  PIN b[254]
    DIRECTION OUTPUT ;
    USE SIGNAL ;
    PORT
      LAYER M4 ;
        RECT  21.516 18.96 21.6 18.984 ;
    END
  END b[254]
  PIN b[255]
    DIRECTION OUTPUT ;
    USE SIGNAL ;
    PORT
      LAYER M4 ;
        RECT  21.516 19.056 21.6 19.08 ;
    END
  END b[255]
  PIN b[256]
    DIRECTION OUTPUT ;
    USE SIGNAL ;
    PORT
      LAYER M4 ;
        RECT  21.516 9.936 21.6 9.96 ;
    END
  END b[256]
  PIN b[257]
    DIRECTION OUTPUT ;
    USE SIGNAL ;
    PORT
      LAYER M4 ;
        RECT  21.516 10.032 21.6 10.056 ;
    END
  END b[257]
  PIN b[258]
    DIRECTION OUTPUT ;
    USE SIGNAL ;
    PORT
      LAYER M4 ;
        RECT  21.516 10.128 21.6 10.152 ;
    END
  END b[258]
  PIN b[259]
    DIRECTION OUTPUT ;
    USE SIGNAL ;
    PORT
      LAYER M4 ;
        RECT  21.516 10.224 21.6 10.248 ;
    END
  END b[259]
  PIN b[25]
    DIRECTION OUTPUT ;
    USE SIGNAL ;
    PORT
      LAYER M4 ;
        RECT  21.516 28.464 21.6 28.488 ;
    END
  END b[25]
  PIN b[260]
    DIRECTION OUTPUT ;
    USE SIGNAL ;
    PORT
      LAYER M4 ;
        RECT  21.516 10.32 21.6 10.344 ;
    END
  END b[260]
  PIN b[261]
    DIRECTION OUTPUT ;
    USE SIGNAL ;
    PORT
      LAYER M4 ;
        RECT  21.516 10.416 21.6 10.44 ;
    END
  END b[261]
  PIN b[262]
    DIRECTION OUTPUT ;
    USE SIGNAL ;
    PORT
      LAYER M4 ;
        RECT  21.516 10.512 21.6 10.536 ;
    END
  END b[262]
  PIN b[263]
    DIRECTION OUTPUT ;
    USE SIGNAL ;
    PORT
      LAYER M4 ;
        RECT  21.516 10.608 21.6 10.632 ;
    END
  END b[263]
  PIN b[264]
    DIRECTION OUTPUT ;
    USE SIGNAL ;
    PORT
      LAYER M4 ;
        RECT  21.516 10.704 21.6 10.728 ;
    END
  END b[264]
  PIN b[265]
    DIRECTION OUTPUT ;
    USE SIGNAL ;
    PORT
      LAYER M4 ;
        RECT  21.516 10.8 21.6 10.824 ;
    END
  END b[265]
  PIN b[266]
    DIRECTION OUTPUT ;
    USE SIGNAL ;
    PORT
      LAYER M4 ;
        RECT  21.516 10.896 21.6 10.92 ;
    END
  END b[266]
  PIN b[267]
    DIRECTION OUTPUT ;
    USE SIGNAL ;
    PORT
      LAYER M4 ;
        RECT  21.516 10.992 21.6 11.016 ;
    END
  END b[267]
  PIN b[268]
    DIRECTION OUTPUT ;
    USE SIGNAL ;
    PORT
      LAYER M4 ;
        RECT  21.516 11.088 21.6 11.112 ;
    END
  END b[268]
  PIN b[269]
    DIRECTION OUTPUT ;
    USE SIGNAL ;
    PORT
      LAYER M4 ;
        RECT  21.516 11.184 21.6 11.208 ;
    END
  END b[269]
  PIN b[26]
    DIRECTION OUTPUT ;
    USE SIGNAL ;
    PORT
      LAYER M4 ;
        RECT  21.516 28.56 21.6 28.584 ;
    END
  END b[26]
  PIN b[270]
    DIRECTION OUTPUT ;
    USE SIGNAL ;
    PORT
      LAYER M4 ;
        RECT  21.516 11.28 21.6 11.304 ;
    END
  END b[270]
  PIN b[271]
    DIRECTION OUTPUT ;
    USE SIGNAL ;
    PORT
      LAYER M4 ;
        RECT  21.516 11.376 21.6 11.4 ;
    END
  END b[271]
  PIN b[27]
    DIRECTION OUTPUT ;
    USE SIGNAL ;
    PORT
      LAYER M4 ;
        RECT  21.516 28.656 21.6 28.68 ;
    END
  END b[27]
  PIN b[28]
    DIRECTION OUTPUT ;
    USE SIGNAL ;
    PORT
      LAYER M4 ;
        RECT  21.516 28.752 21.6 28.776 ;
    END
  END b[28]
  PIN b[29]
    DIRECTION OUTPUT ;
    USE SIGNAL ;
    PORT
      LAYER M4 ;
        RECT  21.516 28.848 21.6 28.872 ;
    END
  END b[29]
  PIN b[2]
    DIRECTION OUTPUT ;
    USE SIGNAL ;
    PORT
      LAYER M4 ;
        RECT  21.516 26.256 21.6 26.28 ;
    END
  END b[2]
  PIN b[30]
    DIRECTION OUTPUT ;
    USE SIGNAL ;
    PORT
      LAYER M4 ;
        RECT  21.516 28.944 21.6 28.968 ;
    END
  END b[30]
  PIN b[31]
    DIRECTION OUTPUT ;
    USE SIGNAL ;
    PORT
      LAYER M4 ;
        RECT  21.516 29.04 21.6 29.064 ;
    END
  END b[31]
  PIN b[32]
    DIRECTION OUTPUT ;
    USE SIGNAL ;
    PORT
      LAYER M4 ;
        RECT  21.516 32.208 21.6 32.232 ;
    END
  END b[32]
  PIN b[33]
    DIRECTION OUTPUT ;
    USE SIGNAL ;
    PORT
      LAYER M4 ;
        RECT  21.516 32.304 21.6 32.328 ;
    END
  END b[33]
  PIN b[34]
    DIRECTION OUTPUT ;
    USE SIGNAL ;
    PORT
      LAYER M4 ;
        RECT  21.516 32.4 21.6 32.424 ;
    END
  END b[34]
  PIN b[35]
    DIRECTION OUTPUT ;
    USE SIGNAL ;
    PORT
      LAYER M4 ;
        RECT  21.516 32.496 21.6 32.52 ;
    END
  END b[35]
  PIN b[36]
    DIRECTION OUTPUT ;
    USE SIGNAL ;
    PORT
      LAYER M4 ;
        RECT  21.516 32.592 21.6 32.616 ;
    END
  END b[36]
  PIN b[37]
    DIRECTION OUTPUT ;
    USE SIGNAL ;
    PORT
      LAYER M4 ;
        RECT  21.516 32.688 21.6 32.712 ;
    END
  END b[37]
  PIN b[38]
    DIRECTION OUTPUT ;
    USE SIGNAL ;
    PORT
      LAYER M4 ;
        RECT  21.516 32.784 21.6 32.808 ;
    END
  END b[38]
  PIN b[39]
    DIRECTION OUTPUT ;
    USE SIGNAL ;
    PORT
      LAYER M4 ;
        RECT  21.516 32.88 21.6 32.904 ;
    END
  END b[39]
  PIN b[3]
    DIRECTION OUTPUT ;
    USE SIGNAL ;
    PORT
      LAYER M4 ;
        RECT  21.516 26.352 21.6 26.376 ;
    END
  END b[3]
  PIN b[40]
    DIRECTION OUTPUT ;
    USE SIGNAL ;
    PORT
      LAYER M4 ;
        RECT  21.516 32.976 21.6 33 ;
    END
  END b[40]
  PIN b[41]
    DIRECTION OUTPUT ;
    USE SIGNAL ;
    PORT
      LAYER M4 ;
        RECT  21.516 33.072 21.6 33.096 ;
    END
  END b[41]
  PIN b[42]
    DIRECTION OUTPUT ;
    USE SIGNAL ;
    PORT
      LAYER M4 ;
        RECT  21.516 33.168 21.6 33.192 ;
    END
  END b[42]
  PIN b[43]
    DIRECTION OUTPUT ;
    USE SIGNAL ;
    PORT
      LAYER M4 ;
        RECT  21.516 33.264 21.6 33.288 ;
    END
  END b[43]
  PIN b[44]
    DIRECTION OUTPUT ;
    USE SIGNAL ;
    PORT
      LAYER M4 ;
        RECT  21.516 33.36 21.6 33.384 ;
    END
  END b[44]
  PIN b[45]
    DIRECTION OUTPUT ;
    USE SIGNAL ;
    PORT
      LAYER M4 ;
        RECT  21.516 33.456 21.6 33.48 ;
    END
  END b[45]
  PIN b[46]
    DIRECTION OUTPUT ;
    USE SIGNAL ;
    PORT
      LAYER M4 ;
        RECT  21.516 33.552 21.6 33.576 ;
    END
  END b[46]
  PIN b[47]
    DIRECTION OUTPUT ;
    USE SIGNAL ;
    PORT
      LAYER M4 ;
        RECT  21.516 33.648 21.6 33.672 ;
    END
  END b[47]
  PIN b[48]
    DIRECTION OUTPUT ;
    USE SIGNAL ;
    PORT
      LAYER M4 ;
        RECT  21.516 33.744 21.6 33.768 ;
    END
  END b[48]
  PIN b[49]
    DIRECTION OUTPUT ;
    USE SIGNAL ;
    PORT
      LAYER M4 ;
        RECT  21.516 33.84 21.6 33.864 ;
    END
  END b[49]
  PIN b[4]
    DIRECTION OUTPUT ;
    USE SIGNAL ;
    PORT
      LAYER M4 ;
        RECT  21.516 26.448 21.6 26.472 ;
    END
  END b[4]
  PIN b[50]
    DIRECTION OUTPUT ;
    USE SIGNAL ;
    PORT
      LAYER M4 ;
        RECT  21.516 33.936 21.6 33.96 ;
    END
  END b[50]
  PIN b[51]
    DIRECTION OUTPUT ;
    USE SIGNAL ;
    PORT
      LAYER M4 ;
        RECT  21.516 34.032 21.6 34.056 ;
    END
  END b[51]
  PIN b[52]
    DIRECTION OUTPUT ;
    USE SIGNAL ;
    PORT
      LAYER M4 ;
        RECT  21.516 34.128 21.6 34.152 ;
    END
  END b[52]
  PIN b[53]
    DIRECTION OUTPUT ;
    USE SIGNAL ;
    PORT
      LAYER M4 ;
        RECT  21.516 34.224 21.6 34.248 ;
    END
  END b[53]
  PIN b[54]
    DIRECTION OUTPUT ;
    USE SIGNAL ;
    PORT
      LAYER M4 ;
        RECT  21.516 34.32 21.6 34.344 ;
    END
  END b[54]
  PIN b[55]
    DIRECTION OUTPUT ;
    USE SIGNAL ;
    PORT
      LAYER M4 ;
        RECT  21.516 34.416 21.6 34.44 ;
    END
  END b[55]
  PIN b[56]
    DIRECTION OUTPUT ;
    USE SIGNAL ;
    PORT
      LAYER M4 ;
        RECT  21.516 34.512 21.6 34.536 ;
    END
  END b[56]
  PIN b[57]
    DIRECTION OUTPUT ;
    USE SIGNAL ;
    PORT
      LAYER M4 ;
        RECT  21.516 34.608 21.6 34.632 ;
    END
  END b[57]
  PIN b[58]
    DIRECTION OUTPUT ;
    USE SIGNAL ;
    PORT
      LAYER M4 ;
        RECT  21.516 34.704 21.6 34.728 ;
    END
  END b[58]
  PIN b[59]
    DIRECTION OUTPUT ;
    USE SIGNAL ;
    PORT
      LAYER M4 ;
        RECT  21.516 34.8 21.6 34.824 ;
    END
  END b[59]
  PIN b[5]
    DIRECTION OUTPUT ;
    USE SIGNAL ;
    PORT
      LAYER M4 ;
        RECT  21.516 26.544 21.6 26.568 ;
    END
  END b[5]
  PIN b[60]
    DIRECTION OUTPUT ;
    USE SIGNAL ;
    PORT
      LAYER M4 ;
        RECT  21.516 34.896 21.6 34.92 ;
    END
  END b[60]
  PIN b[61]
    DIRECTION OUTPUT ;
    USE SIGNAL ;
    PORT
      LAYER M4 ;
        RECT  21.516 34.992 21.6 35.016 ;
    END
  END b[61]
  PIN b[62]
    DIRECTION OUTPUT ;
    USE SIGNAL ;
    PORT
      LAYER M4 ;
        RECT  21.516 35.088 21.6 35.112 ;
    END
  END b[62]
  PIN b[63]
    DIRECTION OUTPUT ;
    USE SIGNAL ;
    PORT
      LAYER M4 ;
        RECT  21.516 35.184 21.6 35.208 ;
    END
  END b[63]
  PIN b[64]
    DIRECTION OUTPUT ;
    USE SIGNAL ;
    PORT
      LAYER M4 ;
        RECT  21.516 29.136 21.6 29.16 ;
    END
  END b[64]
  PIN b[65]
    DIRECTION OUTPUT ;
    USE SIGNAL ;
    PORT
      LAYER M4 ;
        RECT  21.516 29.232 21.6 29.256 ;
    END
  END b[65]
  PIN b[66]
    DIRECTION OUTPUT ;
    USE SIGNAL ;
    PORT
      LAYER M4 ;
        RECT  21.516 29.328 21.6 29.352 ;
    END
  END b[66]
  PIN b[67]
    DIRECTION OUTPUT ;
    USE SIGNAL ;
    PORT
      LAYER M4 ;
        RECT  21.516 29.424 21.6 29.448 ;
    END
  END b[67]
  PIN b[68]
    DIRECTION OUTPUT ;
    USE SIGNAL ;
    PORT
      LAYER M4 ;
        RECT  21.516 29.52 21.6 29.544 ;
    END
  END b[68]
  PIN b[69]
    DIRECTION OUTPUT ;
    USE SIGNAL ;
    PORT
      LAYER M4 ;
        RECT  21.516 29.616 21.6 29.64 ;
    END
  END b[69]
  PIN b[6]
    DIRECTION OUTPUT ;
    USE SIGNAL ;
    PORT
      LAYER M4 ;
        RECT  21.516 26.64 21.6 26.664 ;
    END
  END b[6]
  PIN b[70]
    DIRECTION OUTPUT ;
    USE SIGNAL ;
    PORT
      LAYER M4 ;
        RECT  21.516 29.712 21.6 29.736 ;
    END
  END b[70]
  PIN b[71]
    DIRECTION OUTPUT ;
    USE SIGNAL ;
    PORT
      LAYER M4 ;
        RECT  21.516 29.808 21.6 29.832 ;
    END
  END b[71]
  PIN b[72]
    DIRECTION OUTPUT ;
    USE SIGNAL ;
    PORT
      LAYER M4 ;
        RECT  21.516 29.904 21.6 29.928 ;
    END
  END b[72]
  PIN b[73]
    DIRECTION OUTPUT ;
    USE SIGNAL ;
    PORT
      LAYER M4 ;
        RECT  21.516 30 21.6 30.024 ;
    END
  END b[73]
  PIN b[74]
    DIRECTION OUTPUT ;
    USE SIGNAL ;
    PORT
      LAYER M4 ;
        RECT  21.516 30.096 21.6 30.12 ;
    END
  END b[74]
  PIN b[75]
    DIRECTION OUTPUT ;
    USE SIGNAL ;
    PORT
      LAYER M4 ;
        RECT  21.516 30.192 21.6 30.216 ;
    END
  END b[75]
  PIN b[76]
    DIRECTION OUTPUT ;
    USE SIGNAL ;
    PORT
      LAYER M4 ;
        RECT  21.516 30.288 21.6 30.312 ;
    END
  END b[76]
  PIN b[77]
    DIRECTION OUTPUT ;
    USE SIGNAL ;
    PORT
      LAYER M4 ;
        RECT  21.516 30.384 21.6 30.408 ;
    END
  END b[77]
  PIN b[78]
    DIRECTION OUTPUT ;
    USE SIGNAL ;
    PORT
      LAYER M4 ;
        RECT  21.516 30.48 21.6 30.504 ;
    END
  END b[78]
  PIN b[79]
    DIRECTION OUTPUT ;
    USE SIGNAL ;
    PORT
      LAYER M4 ;
        RECT  21.516 30.576 21.6 30.6 ;
    END
  END b[79]
  PIN b[7]
    DIRECTION OUTPUT ;
    USE SIGNAL ;
    PORT
      LAYER M4 ;
        RECT  21.516 26.736 21.6 26.76 ;
    END
  END b[7]
  PIN b[80]
    DIRECTION OUTPUT ;
    USE SIGNAL ;
    PORT
      LAYER M4 ;
        RECT  21.516 30.672 21.6 30.696 ;
    END
  END b[80]
  PIN b[81]
    DIRECTION OUTPUT ;
    USE SIGNAL ;
    PORT
      LAYER M4 ;
        RECT  21.516 30.768 21.6 30.792 ;
    END
  END b[81]
  PIN b[82]
    DIRECTION OUTPUT ;
    USE SIGNAL ;
    PORT
      LAYER M4 ;
        RECT  21.516 30.864 21.6 30.888 ;
    END
  END b[82]
  PIN b[83]
    DIRECTION OUTPUT ;
    USE SIGNAL ;
    PORT
      LAYER M4 ;
        RECT  21.516 30.96 21.6 30.984 ;
    END
  END b[83]
  PIN b[84]
    DIRECTION OUTPUT ;
    USE SIGNAL ;
    PORT
      LAYER M4 ;
        RECT  21.516 31.056 21.6 31.08 ;
    END
  END b[84]
  PIN b[85]
    DIRECTION OUTPUT ;
    USE SIGNAL ;
    PORT
      LAYER M4 ;
        RECT  21.516 31.152 21.6 31.176 ;
    END
  END b[85]
  PIN b[86]
    DIRECTION OUTPUT ;
    USE SIGNAL ;
    PORT
      LAYER M4 ;
        RECT  21.516 31.248 21.6 31.272 ;
    END
  END b[86]
  PIN b[87]
    DIRECTION OUTPUT ;
    USE SIGNAL ;
    PORT
      LAYER M4 ;
        RECT  21.516 31.344 21.6 31.368 ;
    END
  END b[87]
  PIN b[88]
    DIRECTION OUTPUT ;
    USE SIGNAL ;
    PORT
      LAYER M4 ;
        RECT  21.516 31.44 21.6 31.464 ;
    END
  END b[88]
  PIN b[89]
    DIRECTION OUTPUT ;
    USE SIGNAL ;
    PORT
      LAYER M4 ;
        RECT  21.516 31.536 21.6 31.56 ;
    END
  END b[89]
  PIN b[8]
    DIRECTION OUTPUT ;
    USE SIGNAL ;
    PORT
      LAYER M4 ;
        RECT  21.516 26.832 21.6 26.856 ;
    END
  END b[8]
  PIN b[90]
    DIRECTION OUTPUT ;
    USE SIGNAL ;
    PORT
      LAYER M4 ;
        RECT  21.516 31.632 21.6 31.656 ;
    END
  END b[90]
  PIN b[91]
    DIRECTION OUTPUT ;
    USE SIGNAL ;
    PORT
      LAYER M4 ;
        RECT  21.516 31.728 21.6 31.752 ;
    END
  END b[91]
  PIN b[92]
    DIRECTION OUTPUT ;
    USE SIGNAL ;
    PORT
      LAYER M4 ;
        RECT  21.516 31.824 21.6 31.848 ;
    END
  END b[92]
  PIN b[93]
    DIRECTION OUTPUT ;
    USE SIGNAL ;
    PORT
      LAYER M4 ;
        RECT  21.516 31.92 21.6 31.944 ;
    END
  END b[93]
  PIN b[94]
    DIRECTION OUTPUT ;
    USE SIGNAL ;
    PORT
      LAYER M4 ;
        RECT  21.516 32.016 21.6 32.04 ;
    END
  END b[94]
  PIN b[95]
    DIRECTION OUTPUT ;
    USE SIGNAL ;
    PORT
      LAYER M4 ;
        RECT  21.516 32.112 21.6 32.136 ;
    END
  END b[95]
  PIN b[96]
    DIRECTION OUTPUT ;
    USE SIGNAL ;
    PORT
      LAYER M4 ;
        RECT  21.516 19.92 21.6 19.944 ;
    END
  END b[96]
  PIN b[97]
    DIRECTION OUTPUT ;
    USE SIGNAL ;
    PORT
      LAYER M4 ;
        RECT  21.516 20.016 21.6 20.04 ;
    END
  END b[97]
  PIN b[98]
    DIRECTION OUTPUT ;
    USE SIGNAL ;
    PORT
      LAYER M4 ;
        RECT  21.516 20.112 21.6 20.136 ;
    END
  END b[98]
  PIN b[99]
    DIRECTION OUTPUT ;
    USE SIGNAL ;
    PORT
      LAYER M4 ;
        RECT  21.516 20.208 21.6 20.232 ;
    END
  END b[99]
  PIN b[9]
    DIRECTION OUTPUT ;
    USE SIGNAL ;
    PORT
      LAYER M4 ;
        RECT  21.516 26.928 21.6 26.952 ;
    END
  END b[9]
  PIN ck_o[0]
    DIRECTION OUTPUT ;
    USE SIGNAL ;
    PORT
      LAYER M4 ;
        RECT  21.516 11.472 21.6 11.496 ;
    END
  END ck_o[0]
  PIN ck_o[1]
    DIRECTION OUTPUT ;
    USE SIGNAL ;
    PORT
      LAYER M4 ;
        RECT  21.516 11.568 21.6 11.592 ;
    END
  END ck_o[1]
  PIN ckf
    DIRECTION INPUT ;
    USE SIGNAL ;
    PORT
      LAYER M4 ;
        RECT  0 18.576 0.084 18.6 ;
    END
  END ckf
  PIN ea
    DIRECTION INPUT ;
    USE SIGNAL ;
    PORT
      LAYER M4 ;
        RECT  0 18.672 0.084 18.696 ;
    END
  END ea
  PIN eb[0]
    DIRECTION OUTPUT ;
    USE SIGNAL ;
    PORT
      LAYER M4 ;
        RECT  21.516 11.664 21.6 11.688 ;
    END
  END eb[0]
  PIN eb[1]
    DIRECTION OUTPUT ;
    USE SIGNAL ;
    PORT
      LAYER M4 ;
        RECT  21.516 11.76 21.6 11.784 ;
    END
  END eb[1]
  PIN VDD
    DIRECTION INOUT ;
    USE POWER ;
    PORT
      LAYER M5 ;
        RECT  18.792 2.151 18.912 51.849 ;
        RECT  16.092 2.151 16.212 51.849 ;
        RECT  13.392 2.151 13.512 51.849 ;
        RECT  10.692 2.151 10.812 51.849 ;
        RECT  7.992 2.151 8.112 51.849 ;
        RECT  5.292 2.151 5.412 51.849 ;
        RECT  2.592 2.151 2.712 51.849 ;
    END
  END VDD
  PIN VSS
    DIRECTION INOUT ;
    USE GROUND ;
    PORT
      LAYER M5 ;
        RECT  18.6 2.137 18.72 51.863 ;
        RECT  15.9 2.137 16.02 51.863 ;
        RECT  13.2 2.137 13.32 51.863 ;
        RECT  10.5 2.137 10.62 51.863 ;
        RECT  7.8 2.137 7.92 51.863 ;
        RECT  5.1 2.137 5.22 51.863 ;
        RECT  2.4 2.137 2.52 51.863 ;
    END
  END VSS
  OBS
    LAYER RVTN ;
     RECT  2.16 2.16 19.44 2.295 ;
     RECT  2.16 2.565 19.44 2.835 ;
     RECT  2.16 3.105 19.44 3.375 ;
     RECT  2.16 3.645 19.44 3.915 ;
     RECT  2.16 4.185 19.44 4.455 ;
     RECT  2.16 4.725 19.44 4.995 ;
     RECT  2.16 5.265 19.44 5.535 ;
     RECT  2.16 5.805 19.44 6.075 ;
     RECT  2.16 6.345 19.44 6.615 ;
     RECT  2.16 6.885 19.44 7.155 ;
     RECT  2.16 7.425 19.44 7.695 ;
     RECT  2.16 7.965 19.44 8.235 ;
     RECT  2.16 8.505 19.44 8.775 ;
     RECT  2.16 9.045 19.44 9.315 ;
     RECT  2.16 9.585 19.44 9.855 ;
     RECT  2.16 10.125 19.44 10.395 ;
     RECT  2.16 10.665 19.44 10.935 ;
     RECT  2.16 11.205 19.44 11.475 ;
     RECT  2.16 11.745 19.44 12.015 ;
     RECT  2.16 12.285 19.44 12.555 ;
     RECT  2.16 12.825 19.44 13.095 ;
     RECT  2.16 13.365 19.44 13.635 ;
     RECT  2.16 13.905 19.44 14.175 ;
     RECT  2.16 14.445 19.44 14.715 ;
     RECT  2.16 14.985 19.44 15.255 ;
     RECT  2.16 15.525 19.44 15.795 ;
     RECT  2.16 16.065 19.44 16.335 ;
     RECT  2.16 16.605 19.44 16.875 ;
     RECT  2.16 17.145 19.44 17.415 ;
     RECT  2.16 17.685 19.44 17.955 ;
     RECT  2.16 18.225 19.44 18.495 ;
     RECT  2.16 18.765 19.44 19.035 ;
     RECT  2.16 19.305 19.44 19.575 ;
     RECT  2.16 19.845 19.44 20.115 ;
     RECT  2.16 20.385 19.44 20.655 ;
     RECT  2.16 20.925 19.44 21.195 ;
     RECT  2.16 21.465 19.44 21.735 ;
     RECT  2.16 22.005 19.44 22.275 ;
     RECT  2.16 22.545 19.44 22.815 ;
     RECT  2.16 23.085 19.44 23.355 ;
     RECT  2.16 23.625 19.44 23.895 ;
     RECT  2.16 24.165 19.44 24.435 ;
     RECT  2.16 24.705 19.44 24.975 ;
     RECT  2.16 25.245 19.44 25.515 ;
     RECT  2.16 25.785 19.44 26.055 ;
     RECT  2.16 26.325 19.44 26.595 ;
     RECT  2.16 26.865 19.44 27.135 ;
     RECT  2.16 27.405 19.44 27.675 ;
     RECT  2.16 27.945 19.44 28.215 ;
     RECT  2.16 28.485 19.44 28.755 ;
     RECT  2.16 29.025 19.44 29.295 ;
     RECT  2.16 29.565 19.44 29.835 ;
     RECT  2.16 30.105 19.44 30.375 ;
     RECT  2.16 30.645 19.44 30.915 ;
     RECT  2.16 31.185 19.44 31.455 ;
     RECT  2.16 31.725 19.44 31.995 ;
     RECT  2.16 32.265 19.44 32.535 ;
     RECT  2.16 32.805 19.44 33.075 ;
     RECT  2.16 33.345 19.44 33.615 ;
     RECT  2.16 33.885 19.44 34.155 ;
     RECT  2.16 34.425 19.44 34.695 ;
     RECT  2.16 34.965 19.44 35.235 ;
     RECT  2.16 35.505 19.44 35.775 ;
     RECT  2.16 36.045 19.44 36.315 ;
     RECT  2.16 36.585 19.44 36.855 ;
     RECT  2.16 37.125 19.44 37.395 ;
     RECT  2.16 37.665 19.44 37.935 ;
     RECT  2.16 38.205 19.44 38.475 ;
     RECT  2.16 38.745 19.44 39.015 ;
     RECT  2.16 39.285 19.44 39.555 ;
     RECT  2.16 39.825 19.44 40.095 ;
     RECT  2.16 40.365 19.44 40.635 ;
     RECT  2.16 40.905 19.44 41.175 ;
     RECT  2.16 41.445 19.44 41.715 ;
     RECT  2.16 41.985 19.44 42.255 ;
     RECT  2.16 42.525 19.44 42.795 ;
     RECT  2.16 43.065 19.44 43.335 ;
     RECT  2.16 43.605 19.44 43.875 ;
     RECT  2.16 44.145 19.44 44.415 ;
     RECT  2.16 44.685 19.44 44.955 ;
     RECT  2.16 45.225 19.44 45.495 ;
     RECT  2.16 45.765 19.44 46.035 ;
     RECT  2.16 46.305 19.44 46.575 ;
     RECT  2.16 46.845 19.44 47.115 ;
     RECT  2.16 47.385 19.44 47.655 ;
     RECT  2.16 47.925 19.44 48.195 ;
     RECT  2.16 48.465 19.44 48.735 ;
     RECT  2.16 49.005 19.44 49.275 ;
     RECT  2.16 49.545 19.44 49.815 ;
     RECT  2.16 50.085 19.44 50.355 ;
     RECT  2.16 50.625 19.44 50.895 ;
     RECT  2.16 51.165 19.44 51.435 ;
     RECT  2.16 51.705 19.44 51.84 ;
    LAYER RVTP ;
     RECT  2.16 2.295 19.44 2.565 ;
     RECT  2.16 2.835 19.44 3.105 ;
     RECT  2.16 3.375 19.44 3.645 ;
     RECT  2.16 3.915 19.44 4.185 ;
     RECT  2.16 4.455 19.44 4.725 ;
     RECT  2.16 4.995 19.44 5.265 ;
     RECT  2.16 5.535 19.44 5.805 ;
     RECT  2.16 6.075 19.44 6.345 ;
     RECT  2.16 6.615 19.44 6.885 ;
     RECT  2.16 7.155 19.44 7.425 ;
     RECT  2.16 7.695 19.44 7.965 ;
     RECT  2.16 8.235 19.44 8.505 ;
     RECT  2.16 8.775 19.44 9.045 ;
     RECT  2.16 9.315 19.44 9.585 ;
     RECT  2.16 9.855 19.44 10.125 ;
     RECT  2.16 10.395 19.44 10.665 ;
     RECT  2.16 10.935 19.44 11.205 ;
     RECT  2.16 11.475 19.44 11.745 ;
     RECT  2.16 12.015 19.44 12.285 ;
     RECT  2.16 12.555 19.44 12.825 ;
     RECT  2.16 13.095 19.44 13.365 ;
     RECT  2.16 13.635 19.44 13.905 ;
     RECT  2.16 14.175 19.44 14.445 ;
     RECT  2.16 14.715 19.44 14.985 ;
     RECT  2.16 15.255 19.44 15.525 ;
     RECT  2.16 15.795 19.44 16.065 ;
     RECT  2.16 16.335 19.44 16.605 ;
     RECT  2.16 16.875 19.44 17.145 ;
     RECT  2.16 17.415 19.44 17.685 ;
     RECT  2.16 17.955 19.44 18.225 ;
     RECT  2.16 18.495 19.44 18.765 ;
     RECT  2.16 19.035 19.44 19.305 ;
     RECT  2.16 19.575 19.44 19.845 ;
     RECT  2.16 20.115 19.44 20.385 ;
     RECT  2.16 20.655 19.44 20.925 ;
     RECT  2.16 21.195 19.44 21.465 ;
     RECT  2.16 21.735 19.44 22.005 ;
     RECT  2.16 22.275 19.44 22.545 ;
     RECT  2.16 22.815 19.44 23.085 ;
     RECT  2.16 23.355 19.44 23.625 ;
     RECT  2.16 23.895 19.44 24.165 ;
     RECT  2.16 24.435 19.44 24.705 ;
     RECT  2.16 24.975 19.44 25.245 ;
     RECT  2.16 25.515 19.44 25.785 ;
     RECT  2.16 26.055 19.44 26.325 ;
     RECT  2.16 26.595 19.44 26.865 ;
     RECT  2.16 27.135 19.44 27.405 ;
     RECT  2.16 27.675 19.44 27.945 ;
     RECT  2.16 28.215 19.44 28.485 ;
     RECT  2.16 28.755 19.44 29.025 ;
     RECT  2.16 29.295 19.44 29.565 ;
     RECT  2.16 29.835 19.44 30.105 ;
     RECT  2.16 30.375 19.44 30.645 ;
     RECT  2.16 30.915 19.44 31.185 ;
     RECT  2.16 31.455 19.44 31.725 ;
     RECT  2.16 31.995 19.44 32.265 ;
     RECT  2.16 32.535 19.44 32.805 ;
     RECT  2.16 33.075 19.44 33.345 ;
     RECT  2.16 33.615 19.44 33.885 ;
     RECT  2.16 34.155 19.44 34.425 ;
     RECT  2.16 34.695 19.44 34.965 ;
     RECT  2.16 35.235 19.44 35.505 ;
     RECT  2.16 35.775 19.44 36.045 ;
     RECT  2.16 36.315 19.44 36.585 ;
     RECT  2.16 36.855 19.44 37.125 ;
     RECT  2.16 37.395 19.44 37.665 ;
     RECT  2.16 37.935 19.44 38.205 ;
     RECT  2.16 38.475 19.44 38.745 ;
     RECT  2.16 39.015 19.44 39.285 ;
     RECT  2.16 39.555 19.44 39.825 ;
     RECT  2.16 40.095 19.44 40.365 ;
     RECT  2.16 40.635 19.44 40.905 ;
     RECT  2.16 41.175 19.44 41.445 ;
     RECT  2.16 41.715 19.44 41.985 ;
     RECT  2.16 42.255 19.44 42.525 ;
     RECT  2.16 42.795 19.44 43.065 ;
     RECT  2.16 43.335 19.44 43.605 ;
     RECT  2.16 43.875 19.44 44.145 ;
     RECT  2.16 44.415 19.44 44.685 ;
     RECT  2.16 44.955 19.44 45.225 ;
     RECT  2.16 45.495 19.44 45.765 ;
     RECT  2.16 46.035 19.44 46.305 ;
     RECT  2.16 46.575 19.44 46.845 ;
     RECT  2.16 47.115 19.44 47.385 ;
     RECT  2.16 47.655 19.44 47.925 ;
     RECT  2.16 48.195 19.44 48.465 ;
     RECT  2.16 48.735 19.44 49.005 ;
     RECT  2.16 49.275 19.44 49.545 ;
     RECT  2.16 49.815 19.44 50.085 ;
     RECT  2.16 50.355 19.44 50.625 ;
     RECT  2.16 50.895 19.44 51.165 ;
     RECT  2.16 51.435 19.44 51.705 ;
    LAYER M1 ;
     RECT  2.16 2.151 19.44 51.849 ;
    LAYER M2 ;
     RECT  0.103 29.61 0.139 30.096 ;
     RECT  0.103 19.584 0.203 19.602 ;
     RECT  0.103 23.094 0.203 23.112 ;
     RECT  0.139 29.61 0.203 30.204 ;
     RECT  0.203 30.078 0.239 30.204 ;
     RECT  0.239 30.078 0.383 30.096 ;
     RECT  0.175 18.666 0.419 18.684 ;
     RECT  0.463 17.694 0.535 17.712 ;
     RECT  0.535 17.658 2.16 17.712 ;
     RECT  0.535 18.738 2.16 18.756 ;
     RECT  0.103 22.212 2.16 22.23 ;
     RECT  2.16 2.151 19.44 51.849 ;
     RECT  19.44 10.026 19.535 38.034 ;
     RECT  19.535 10.026 19.679 36.612 ;
     RECT  19.679 10.026 19.931 13.824 ;
     RECT  19.679 14.652 20.219 36.612 ;
     RECT  20.219 33.048 20.291 36.612 ;
     RECT  19.931 10.026 20.471 12.474 ;
     RECT  19.931 13.266 20.471 13.824 ;
     RECT  20.219 14.652 20.471 31.914 ;
     RECT  20.471 10.296 20.507 10.854 ;
     RECT  20.471 11.646 20.507 11.934 ;
     RECT  20.471 13.446 20.507 13.464 ;
     RECT  20.471 14.796 20.507 31.914 ;
     RECT  19.535 37.404 20.507 38.034 ;
     RECT  20.507 14.796 20.543 14.976 ;
     RECT  20.291 33.156 20.543 36.612 ;
     RECT  20.507 37.404 20.543 37.62 ;
     RECT  20.507 15.966 20.579 23.346 ;
     RECT  20.507 24.174 20.579 31.914 ;
     RECT  20.579 24.174 20.615 30.636 ;
     RECT  20.543 14.958 20.687 14.976 ;
     RECT  20.579 21.546 21.307 23.346 ;
     RECT  21.307 21.474 21.415 23.346 ;
     RECT  20.615 24.174 21.415 30.204 ;
     RECT  20.543 37.476 21.415 37.62 ;
     RECT  20.579 15.966 21.443 20.412 ;
     RECT  21.443 15.966 21.479 15.984 ;
     RECT  21.443 16.776 21.479 18.594 ;
     RECT  21.415 21.474 21.479 30.204 ;
     RECT  20.579 31.662 21.479 31.914 ;
     RECT  21.443 19.584 21.515 20.412 ;
     RECT  21.479 21.816 21.515 23.184 ;
     RECT  21.479 24.066 21.515 25.974 ;
     RECT  21.479 26.766 21.515 27.36 ;
     RECT  21.479 28.116 21.515 28.782 ;
     RECT  21.479 29.916 21.515 30.204 ;
     RECT  21.479 31.896 21.515 31.914 ;
     RECT  20.543 33.354 21.515 35.334 ;
     RECT  20.543 36.594 21.515 36.612 ;
     RECT  21.415 37.476 21.515 37.764 ;
     RECT  21.479 17.496 21.551 17.514 ;
     RECT  21.515 22.356 21.551 22.806 ;
     RECT  21.451 14.454 21.587 14.472 ;
     RECT  21.551 22.356 21.587 22.374 ;
    LAYER M3 ;
     RECT  2.415 2.143 2.505 2.413 ;
     RECT  5.115 2.143 5.205 2.413 ;
     RECT  7.815 2.143 7.905 2.413 ;
     RECT  10.515 2.143 10.605 2.413 ;
     RECT  13.215 2.143 13.305 2.413 ;
     RECT  15.915 2.143 16.005 2.413 ;
     RECT  18.615 2.143 18.705 2.413 ;
     RECT  20.484 9.931 20.502 10.021 ;
     RECT  18.615 2.413 18.897 10.165 ;
     RECT  18.615 10.165 19.494 10.219 ;
     RECT  20.448 10.021 20.502 10.219 ;
     RECT  18.615 10.219 20.502 10.435 ;
     RECT  17.892 10.435 20.502 11.245 ;
     RECT  17.856 11.245 20.502 11.939 ;
     RECT  17.856 11.939 20.466 12.361 ;
     RECT  17.784 12.361 20.466 12.749 ;
     RECT  20.448 12.749 20.466 13.003 ;
     RECT  17.784 12.749 19.674 13.339 ;
     RECT  17.28 13.339 19.674 13.567 ;
     RECT  20.448 13.003 20.502 13.567 ;
     RECT  17.28 13.567 20.502 13.675 ;
     RECT  17.1 13.675 20.502 13.867 ;
     RECT  21.492 14.251 21.51 14.44 ;
     RECT  21.456 14.44 21.51 14.449 ;
     RECT  21.456 14.449 21.582 14.477 ;
     RECT  17.1 13.867 20.538 14.953 ;
     RECT  21.492 14.477 21.582 15.307 ;
     RECT  15.915 2.413 16.197 15.403 ;
     RECT  17.1 14.953 20.682 15.403 ;
     RECT  21.456 15.307 21.582 15.691 ;
     RECT  15.915 15.403 20.682 15.869 ;
     RECT  17.064 15.869 20.682 17.113 ;
     RECT  21.42 15.691 21.582 17.113 ;
     RECT  0.54 17.653 0.558 17.689 ;
     RECT  5.115 2.413 5.397 17.689 ;
     RECT  10.515 2.413 10.797 17.689 ;
     RECT  17.064 17.113 21.582 17.689 ;
     RECT  5.115 17.689 6.066 17.725 ;
     RECT  4.572 17.725 6.066 17.761 ;
     RECT  2.415 2.413 2.697 17.803 ;
     RECT  7.815 2.413 8.097 17.851 ;
     RECT  9.18 17.725 9.198 17.851 ;
     RECT  10.515 17.689 11.394 17.851 ;
     RECT  7.815 17.851 9.198 17.879 ;
     RECT  15.915 15.869 16.197 17.923 ;
     RECT  0.468 17.689 0.558 17.933 ;
     RECT  15.876 17.923 16.197 17.959 ;
     RECT  7.815 17.879 9.126 17.989 ;
     RECT  4.176 17.761 6.066 17.995 ;
     RECT  7.74 17.989 9.126 17.995 ;
     RECT  10.515 17.851 11.97 18.031 ;
     RECT  10.476 18.031 11.97 18.121 ;
     RECT  15.516 17.959 16.197 18.121 ;
     RECT  4.176 17.995 6.57 18.149 ;
     RECT  14.832 18.121 16.197 18.149 ;
     RECT  4.176 18.149 6.426 18.173 ;
     RECT  6.156 18.173 6.426 18.185 ;
     RECT  7.416 17.995 9.126 18.185 ;
     RECT  10.332 18.121 11.97 18.185 ;
     RECT  10.332 18.185 11.502 18.221 ;
     RECT  0.468 17.933 0.486 18.235 ;
     RECT  15.915 18.149 16.197 18.265 ;
     RECT  16.92 17.689 21.582 18.265 ;
     RECT  10.404 18.221 10.818 18.269 ;
     RECT  2.304 17.803 2.697 18.301 ;
     RECT  2.304 18.301 3.258 18.391 ;
     RECT  4.176 18.173 5.397 18.391 ;
     RECT  9.036 18.185 9.126 18.419 ;
     RECT  9.036 18.419 9.054 18.461 ;
     RECT  0.216 18.235 0.486 18.571 ;
     RECT  0.18 18.571 0.486 18.689 ;
     RECT  15.915 18.265 21.582 18.689 ;
     RECT  0.396 18.689 0.486 18.701 ;
     RECT  7.416 18.185 8.097 18.805 ;
     RECT  13.215 2.413 13.497 18.805 ;
     RECT  13.215 18.805 13.95 18.841 ;
     RECT  14.832 18.149 14.958 18.841 ;
     RECT  0.54 18.733 0.558 18.893 ;
     RECT  6.156 18.185 6.174 18.955 ;
     RECT  7.236 18.805 8.097 18.967 ;
     RECT  13.215 18.841 14.958 18.995 ;
     RECT  10.515 18.269 10.818 19.031 ;
     RECT  7.056 18.967 8.097 19.051 ;
     RECT  6.156 18.955 6.318 19.111 ;
     RECT  7.056 19.051 8.37 19.111 ;
     RECT  2.304 18.391 5.397 19.201 ;
     RECT  6.156 19.111 8.37 19.201 ;
     RECT  13.215 18.995 14.886 19.301 ;
     RECT  14.832 19.301 14.886 19.337 ;
     RECT  2.304 19.201 8.478 19.387 ;
     RECT  2.232 19.387 8.478 19.535 ;
     RECT  0.324 19.435 0.342 19.564 ;
     RECT  0.108 19.564 0.342 19.565 ;
     RECT  2.304 19.535 8.478 19.571 ;
     RECT  4.176 19.571 8.478 19.579 ;
     RECT  15.915 18.689 16.197 19.615 ;
     RECT  16.992 18.689 21.582 19.615 ;
     RECT  0.108 19.565 0.198 19.757 ;
     RECT  4.176 19.579 8.586 19.769 ;
     RECT  0.144 19.757 0.198 19.805 ;
     RECT  14.832 19.337 14.85 19.913 ;
     RECT  9.396 19.849 9.414 19.949 ;
     RECT  6.768 19.769 7.074 20.075 ;
     RECT  6.768 20.075 6.93 20.093 ;
     RECT  0.144 19.805 0.162 20.237 ;
     RECT  9.324 20.389 9.342 20.489 ;
     RECT  2.304 19.571 3.33 20.587 ;
     RECT  4.176 19.769 5.958 20.587 ;
     RECT  2.304 20.587 5.958 20.821 ;
     RECT  6.84 20.093 6.93 20.821 ;
     RECT  7.815 19.769 8.442 20.821 ;
     RECT  10.515 19.031 10.797 20.821 ;
     RECT  2.304 20.821 5.994 20.921 ;
     RECT  3.492 20.921 5.994 20.957 ;
     RECT  14.868 20.389 14.922 21.091 ;
     RECT  3.924 20.957 5.994 21.115 ;
     RECT  6.84 20.821 9.126 21.115 ;
     RECT  10.515 20.821 10.926 21.115 ;
     RECT  14.868 21.091 14.958 21.227 ;
     RECT  14.904 21.227 14.958 21.271 ;
     RECT  3.924 21.115 9.126 21.299 ;
     RECT  3.996 21.299 9.126 21.361 ;
     RECT  0.18 21.211 0.198 21.389 ;
     RECT  14.904 21.271 15.174 21.389 ;
     RECT  10.515 21.115 11.43 21.451 ;
     RECT  3.996 21.361 9.198 21.461 ;
     RECT  3.996 21.461 8.73 21.497 ;
     RECT  2.304 20.921 2.697 21.532 ;
     RECT  10.404 21.451 11.43 21.541 ;
     RECT  3.996 21.497 5.886 21.659 ;
     RECT  6.66 21.497 8.73 21.659 ;
     RECT  10.404 21.541 11.718 21.659 ;
     RECT  2.268 21.532 2.697 21.695 ;
     RECT  1.368 21.643 1.386 21.739 ;
     RECT  1.152 21.739 1.386 21.773 ;
     RECT  6.696 21.659 8.19 21.803 ;
     RECT  14.904 21.389 14.994 22.009 ;
     RECT  1.152 21.773 1.314 22.013 ;
     RECT  2.304 21.695 2.697 22.027 ;
     RECT  14.832 22.009 14.994 22.037 ;
     RECT  3.996 21.659 5.706 22.045 ;
     RECT  1.296 22.013 1.314 22.157 ;
     RECT  2.304 22.027 2.718 22.171 ;
     RECT  3.492 22.045 5.706 22.171 ;
     RECT  6.696 21.803 7.074 22.199 ;
     RECT  0.108 22.207 0.126 22.253 ;
     RECT  15.915 19.615 21.582 22.379 ;
     RECT  0.144 22.363 0.234 22.411 ;
     RECT  0.144 22.411 0.342 22.541 ;
     RECT  2.304 22.171 5.706 22.549 ;
     RECT  7.815 21.803 8.19 22.585 ;
     RECT  7.815 22.585 8.298 22.621 ;
     RECT  7.815 22.621 8.91 22.747 ;
     RECT  13.215 19.301 13.497 22.747 ;
     RECT  7.815 22.747 8.946 22.795 ;
     RECT  15.915 22.379 21.546 22.811 ;
     RECT  7.776 22.795 9.018 22.891 ;
     RECT  12.168 22.819 12.186 22.891 ;
     RECT  12.096 22.891 12.186 22.919 ;
     RECT  2.304 22.549 5.742 22.981 ;
     RECT  6.696 22.199 6.894 22.981 ;
     RECT  7.776 22.891 9.126 23.009 ;
     RECT  14.832 22.037 14.958 23.017 ;
     RECT  15.915 22.811 21.51 23.017 ;
     RECT  0.144 22.541 0.198 23.089 ;
     RECT  2.304 22.981 6.894 23.089 ;
     RECT  7.776 23.009 9.09 23.089 ;
     RECT  12.096 22.919 12.114 23.089 ;
     RECT  13.215 22.747 13.698 23.089 ;
     RECT  12.024 23.089 12.114 23.117 ;
     RECT  2.304 23.089 9.09 23.153 ;
     RECT  12.024 23.117 12.042 23.161 ;
     RECT  0.108 23.089 0.198 23.165 ;
     RECT  0.108 23.165 0.126 23.213 ;
     RECT  2.304 23.153 9.054 23.279 ;
     RECT  13.104 23.089 13.698 23.593 ;
     RECT  14.832 23.017 21.51 23.593 ;
     RECT  2.304 23.279 7.038 23.693 ;
     RECT  10.515 21.659 10.797 23.701 ;
     RECT  13.104 23.593 21.51 23.819 ;
     RECT  13.104 23.819 13.497 23.927 ;
     RECT  2.304 23.693 6.102 23.933 ;
     RECT  10.26 23.701 10.797 23.935 ;
     RECT  11.988 23.161 12.042 23.935 ;
     RECT  10.26 23.935 12.042 24.089 ;
     RECT  7.02 23.693 7.038 24.133 ;
     RECT  7.815 23.279 9.054 24.133 ;
     RECT  10.515 24.089 12.042 24.161 ;
     RECT  7.02 24.133 9.054 24.205 ;
     RECT  7.02 24.205 9.198 24.395 ;
     RECT  0.324 24.331 0.342 24.461 ;
     RECT  3.816 23.933 6.102 24.475 ;
     RECT  10.515 24.161 12.006 24.539 ;
     RECT  3.816 24.475 6.138 24.601 ;
     RECT  7.02 24.395 9.126 24.601 ;
     RECT  14.256 23.819 21.51 24.629 ;
     RECT  3.816 24.601 9.126 24.665 ;
     RECT  14.256 24.629 14.886 24.737 ;
     RECT  14.256 24.737 14.85 24.899 ;
     RECT  2.304 23.933 2.697 25.321 ;
     RECT  13.215 23.927 13.497 25.321 ;
     RECT  14.256 24.899 14.31 25.321 ;
     RECT  2.304 25.321 3.15 25.411 ;
     RECT  3.996 24.665 9.126 25.411 ;
     RECT  11.988 24.539 12.006 25.439 ;
     RECT  13.215 25.321 14.31 25.439 ;
     RECT  10.515 24.539 10.854 25.447 ;
     RECT  10.515 25.447 10.926 25.547 ;
     RECT  2.304 25.411 3.222 25.591 ;
     RECT  1.152 25.435 1.17 25.613 ;
     RECT  2.304 25.591 3.258 25.681 ;
     RECT  3.996 25.411 9.198 25.681 ;
     RECT  15.156 25.519 15.174 25.717 ;
     RECT  15.915 24.629 21.51 25.717 ;
     RECT  0.144 24.811 0.162 25.819 ;
     RECT  15.156 25.717 21.51 25.861 ;
     RECT  2.304 25.681 9.198 25.889 ;
     RECT  14.508 25.861 21.51 25.979 ;
     RECT  0.144 25.819 0.234 25.997 ;
     RECT  14.688 25.979 21.474 26.087 ;
     RECT  6.516 25.889 9.198 26.159 ;
     RECT  14.976 26.087 21.474 26.621 ;
     RECT  14.976 26.621 20.61 26.669 ;
     RECT  21.42 26.621 21.474 26.761 ;
     RECT  2.304 25.889 5.562 26.789 ;
     RECT  6.516 26.159 9.126 26.789 ;
     RECT  2.304 26.789 3.186 26.825 ;
     RECT  3.996 26.789 5.562 26.941 ;
     RECT  6.516 26.789 7.074 26.941 ;
     RECT  0.144 25.997 0.162 27.053 ;
     RECT  14.976 26.669 20.574 27.059 ;
     RECT  10.515 25.547 10.797 27.067 ;
     RECT  3.996 26.941 7.074 27.095 ;
     RECT  10.515 27.067 10.926 27.167 ;
     RECT  15.624 27.059 20.574 27.329 ;
     RECT  3.996 27.095 7.002 27.352 ;
     RECT  3.996 27.352 4.374 27.365 ;
     RECT  14.832 27.301 14.85 27.599 ;
     RECT  21.42 26.761 21.51 27.725 ;
     RECT  2.304 26.825 2.754 27.835 ;
     RECT  5.115 27.352 7.002 27.835 ;
     RECT  5.115 27.835 7.038 27.877 ;
     RECT  7.815 26.789 9.126 27.877 ;
     RECT  10.515 27.167 10.797 27.985 ;
     RECT  15.915 27.329 20.574 28.013 ;
     RECT  5.115 27.877 9.126 28.139 ;
     RECT  10.515 27.985 10.854 28.139 ;
     RECT  4.32 27.365 4.374 28.147 ;
     RECT  5.115 28.139 5.886 28.147 ;
     RECT  13.215 25.439 13.554 28.381 ;
     RECT  14.292 28.291 14.31 28.381 ;
     RECT  4.32 28.147 5.886 28.409 ;
     RECT  6.66 28.139 9.126 28.409 ;
     RECT  1.152 28.171 1.17 28.445 ;
     RECT  6.696 28.409 9.126 28.525 ;
     RECT  2.304 27.835 3.402 28.561 ;
     RECT  4.32 28.409 5.742 28.561 ;
     RECT  0.144 28.507 0.162 28.685 ;
     RECT  15.915 28.013 20.538 28.685 ;
     RECT  2.304 28.561 5.742 28.715 ;
     RECT  13.215 28.381 14.922 28.759 ;
     RECT  13.215 28.759 15.138 28.831 ;
     RECT  15.915 28.685 16.362 28.831 ;
     RECT  6.696 28.525 9.414 28.949 ;
     RECT  13.215 28.831 16.362 28.949 ;
     RECT  21.456 27.725 21.51 28.993 ;
     RECT  14.292 28.949 15.102 29.021 ;
     RECT  21.42 28.993 21.51 29.029 ;
     RECT  3.78 28.715 5.742 29.057 ;
     RECT  3.996 29.057 5.742 29.191 ;
     RECT  6.696 28.949 6.714 29.191 ;
     RECT  17.1 28.685 20.538 29.191 ;
     RECT  17.1 29.191 20.61 29.227 ;
     RECT  21.384 29.029 21.51 29.227 ;
     RECT  7.56 28.949 9.414 29.263 ;
     RECT  7.56 29.263 9.774 29.363 ;
     RECT  2.304 28.715 2.697 29.515 ;
     RECT  0.144 29.419 0.162 29.596 ;
     RECT  17.1 29.227 21.51 29.645 ;
     RECT  7.56 29.363 9.702 29.759 ;
     RECT  14.904 29.021 15.102 29.767 ;
     RECT  15.915 28.949 16.197 29.767 ;
     RECT  7.596 29.759 8.406 29.795 ;
     RECT  0.108 29.596 0.198 29.803 ;
     RECT  14.58 29.767 16.197 29.803 ;
     RECT  3.996 29.191 6.714 30.001 ;
     RECT  3.996 30.001 6.822 30.029 ;
     RECT  9.144 29.759 9.702 30.029 ;
     RECT  2.304 29.515 2.97 30.091 ;
     RECT  0.108 29.803 0.378 30.101 ;
     RECT  14.508 29.803 16.197 30.109 ;
     RECT  17.1 29.645 20.61 30.109 ;
     RECT  0.108 30.101 0.342 30.125 ;
     RECT  9.144 30.029 9.198 30.137 ;
     RECT  0.144 30.125 0.234 30.209 ;
     RECT  0.144 30.209 0.198 30.221 ;
     RECT  21.42 29.645 21.51 30.509 ;
     RECT  4.356 30.029 6.822 30.619 ;
     RECT  7.596 29.795 8.226 30.619 ;
     RECT  21.42 30.509 21.438 30.701 ;
     RECT  4.356 30.619 8.226 30.721 ;
     RECT  9.144 30.137 9.162 30.721 ;
     RECT  14.508 30.109 20.61 30.763 ;
     RECT  2.304 30.091 3.438 30.875 ;
     RECT  4.356 30.721 8.298 30.875 ;
     RECT  14.508 30.763 21.294 30.893 ;
     RECT  0.18 30.221 0.198 30.941 ;
     RECT  4.356 30.875 5.526 30.955 ;
     RECT  2.304 30.875 2.697 30.983 ;
     RECT  14.508 30.893 20.61 30.992 ;
     RECT  3.996 30.955 5.526 31.253 ;
     RECT  3.996 31.253 5.397 31.415 ;
     RECT  7.524 30.875 8.298 31.451 ;
     RECT  4.32 31.415 5.397 31.649 ;
     RECT  4.392 31.649 5.397 31.829 ;
     RECT  21.456 31.657 21.474 31.891 ;
     RECT  21.456 31.891 21.51 32.429 ;
     RECT  14.508 30.992 20.574 32.459 ;
     RECT  21.42 32.539 21.438 32.717 ;
     RECT  15.66 32.459 16.326 32.999 ;
     RECT  17.1 32.459 20.574 32.999 ;
     RECT  15.915 32.999 16.326 33.071 ;
     RECT  6.336 30.875 6.57 33.179 ;
     RECT  17.208 32.999 20.574 33.269 ;
     RECT  9.072 30.721 9.162 33.449 ;
     RECT  14.508 32.459 14.526 33.539 ;
     RECT  4.5 31.829 5.397 33.809 ;
     RECT  21.492 33.349 21.51 33.817 ;
     RECT  15.915 33.071 16.197 33.889 ;
     RECT  15.915 33.889 16.326 33.961 ;
     RECT  7.524 31.451 8.097 33.989 ;
     RECT  21.456 33.817 21.51 34.006 ;
     RECT  17.496 33.269 20.574 34.051 ;
     RECT  6.336 33.179 6.354 34.079 ;
     RECT  15.915 33.961 16.506 34.079 ;
     RECT  17.496 34.051 20.682 34.231 ;
     RECT  21.42 34.006 21.51 34.253 ;
     RECT  9.072 33.449 9.09 34.259 ;
     RECT  17.244 34.231 20.682 34.349 ;
     RECT  17.496 34.349 20.682 34.829 ;
     RECT  21.456 34.253 21.51 35.239 ;
     RECT  21.42 35.239 21.51 35.339 ;
     RECT  17.496 34.829 20.574 35.465 ;
     RECT  21.42 35.339 21.474 35.501 ;
     RECT  21.42 35.501 21.438 35.597 ;
     RECT  17.964 35.465 20.574 35.885 ;
     RECT  17.964 35.885 20.538 36.419 ;
     RECT  17.964 36.419 19.962 36.461 ;
     RECT  21.42 36.571 21.438 36.589 ;
     RECT  17.964 36.461 19.926 36.653 ;
     RECT  21.42 36.589 21.51 36.749 ;
     RECT  17.964 36.653 19.53 36.815 ;
     RECT  21.492 36.749 21.51 37.597 ;
     RECT  17.964 36.815 19.422 37.613 ;
     RECT  17.964 37.613 19.386 37.625 ;
     RECT  18.36 37.625 19.386 37.661 ;
     RECT  18.468 37.661 19.386 37.697 ;
     RECT  20.52 37.399 20.538 37.709 ;
     RECT  21.456 37.597 21.51 37.723 ;
     RECT  21.42 37.723 21.51 37.769 ;
     RECT  21.456 37.769 21.51 37.805 ;
     RECT  18.468 37.697 19.314 37.901 ;
     RECT  20.484 38.011 20.502 38.093 ;
     RECT  21.456 37.805 21.474 38.189 ;
     RECT  18.615 37.901 19.314 38.285 ;
     RECT  2.415 30.983 2.697 51.587 ;
     RECT  5.115 33.809 5.397 51.587 ;
     RECT  7.815 33.989 8.097 51.587 ;
     RECT  10.515 28.139 10.797 51.587 ;
     RECT  13.215 28.949 13.497 51.587 ;
     RECT  15.915 34.079 16.197 51.587 ;
     RECT  18.615 38.285 18.897 51.587 ;
     RECT  2.415 51.587 2.505 51.857 ;
     RECT  5.115 51.587 5.205 51.857 ;
     RECT  7.815 51.587 7.905 51.857 ;
     RECT  10.515 51.587 10.605 51.857 ;
     RECT  13.215 51.587 13.305 51.857 ;
     RECT  15.915 51.587 16.005 51.857 ;
     RECT  18.615 51.587 18.705 51.857 ;
    LAYER M4 ;
     RECT  0.06 17.808 2.408 30.984 ;
     RECT  2.408 2.148 2.512 51.852 ;
     RECT  2.512 2.418 2.704 51.582 ;
     RECT  2.704 18 4.025 30.984 ;
     RECT  4.025 18 5.108 30.84 ;
     RECT  5.108 2.148 5.212 51.852 ;
     RECT  5.212 2.418 5.404 51.582 ;
     RECT  5.404 20.064 5.573 30.648 ;
     RECT  5.573 20.064 5.717 26.376 ;
     RECT  5.717 20.064 5.933 22.2 ;
     RECT  5.717 23.376 6.473 25.032 ;
     RECT  5.404 18 6.649 18.984 ;
     RECT  5.933 20.064 6.649 20.088 ;
     RECT  6.473 23.52 6.685 25.032 ;
     RECT  5.717 26.256 6.685 26.376 ;
     RECT  5.573 27.648 6.685 30.648 ;
     RECT  5.933 21.12 6.689 22.2 ;
     RECT  6.685 26.256 6.721 30.648 ;
     RECT  6.649 18 6.797 20.088 ;
     RECT  6.685 23.52 6.829 25.128 ;
     RECT  6.721 26.256 6.829 30.792 ;
     RECT  6.689 21.216 7.765 22.2 ;
     RECT  6.829 23.52 7.765 30.792 ;
     RECT  6.797 18 7.808 19.512 ;
     RECT  7.765 21.216 7.808 30.792 ;
     RECT  7.808 2.148 7.912 51.852 ;
     RECT  7.912 2.418 8.104 51.582 ;
     RECT  8.104 25.2 8.129 26.376 ;
     RECT  8.104 28.176 8.129 28.44 ;
     RECT  8.129 28.176 8.345 28.2 ;
     RECT  8.104 22.8 8.381 23.976 ;
     RECT  8.104 17.952 8.489 19.272 ;
     RECT  8.129 25.776 8.813 26.376 ;
     RECT  8.813 25.776 8.957 25.8 ;
     RECT  8.381 22.8 9.029 23.016 ;
     RECT  8.489 17.952 9.065 18.456 ;
     RECT  9.029 22.992 9.101 23.016 ;
     RECT  8.104 21.168 9.137 21.48 ;
     RECT  9.137 21.456 10.309 21.48 ;
     RECT  9.065 17.952 10.508 18.264 ;
     RECT  10.309 21.12 10.508 21.48 ;
     RECT  10.508 2.148 10.612 51.852 ;
     RECT  10.612 2.418 10.804 51.582 ;
     RECT  10.804 21.12 11.441 21.144 ;
     RECT  10.804 18.192 11.513 18.216 ;
     RECT  11.941 18.144 13.208 18.168 ;
     RECT  13.208 2.148 13.312 51.852 ;
     RECT  13.312 2.418 13.504 51.582 ;
     RECT  13.504 18.144 15.908 18.168 ;
     RECT  14.821 22.032 15.908 22.056 ;
     RECT  14.965 26.256 15.908 26.28 ;
     RECT  13.504 28.704 15.908 28.728 ;
     RECT  15.908 2.148 16.012 51.852 ;
     RECT  16.012 2.418 16.204 51.582 ;
     RECT  16.204 18.144 16.499 18.168 ;
     RECT  16.204 15.408 16.561 16.008 ;
     RECT  16.204 13.68 17.269 13.704 ;
     RECT  16.204 24.864 17.269 24.888 ;
     RECT  16.204 26.112 17.269 26.616 ;
     RECT  17.269 24.864 17.377 26.616 ;
     RECT  16.204 28.656 17.485 28.728 ;
     RECT  17.269 13.344 17.737 13.704 ;
     RECT  17.485 28.656 17.737 28.824 ;
     RECT  17.377 24.72 17.773 26.616 ;
     RECT  17.773 21.12 17.804 21.144 ;
     RECT  17.521 22.8 17.809 22.824 ;
     RECT  17.773 23.952 17.809 26.616 ;
     RECT  17.737 13.344 18.061 13.896 ;
     RECT  17.804 20.832 18.097 21.144 ;
     RECT  18.097 19.872 18.241 21.144 ;
     RECT  17.809 22.8 18.241 26.616 ;
     RECT  17.737 27.936 18.241 28.824 ;
     RECT  18.061 30.72 18.241 30.744 ;
     RECT  18.097 18.192 18.313 18.744 ;
     RECT  18.241 22.8 18.313 28.824 ;
     RECT  17.917 34.08 18.341 34.104 ;
     RECT  18.313 17.952 18.349 18.744 ;
     RECT  18.241 19.872 18.349 21.432 ;
     RECT  18.277 32.304 18.373 32.328 ;
     RECT  18.341 34.032 18.373 34.104 ;
     RECT  18.241 30.336 18.38 30.744 ;
     RECT  18.38 30.288 18.413 30.744 ;
     RECT  18.313 22.8 18.457 29.064 ;
     RECT  18.349 37.632 18.457 37.656 ;
     RECT  18.373 32.304 18.469 34.104 ;
     RECT  18.349 17.952 18.529 21.432 ;
     RECT  18.457 22.8 18.529 29.256 ;
     RECT  16.204 11.952 18.608 11.976 ;
     RECT  18.061 13.296 18.608 13.896 ;
     RECT  16.561 15.792 18.608 16.008 ;
     RECT  18.529 17.952 18.608 29.256 ;
     RECT  18.413 30.288 18.608 30.792 ;
     RECT  18.469 32.304 18.608 34.248 ;
     RECT  18.565 36.576 18.608 36.6 ;
     RECT  18.457 37.632 18.608 37.896 ;
     RECT  18.608 2.148 18.712 51.852 ;
     RECT  18.712 2.418 18.904 51.582 ;
     RECT  18.904 13.104 19.109 22.152 ;
     RECT  19.109 19.872 19.145 22.152 ;
     RECT  19.109 13.104 19.253 18.744 ;
     RECT  19.253 13.2 19.397 18.744 ;
     RECT  18.904 10.512 19.897 11.592 ;
     RECT  18.904 23.856 19.933 38.28 ;
     RECT  19.145 20.208 20.005 22.152 ;
     RECT  19.933 23.76 20.005 38.28 ;
     RECT  19.897 10.224 20.401 11.592 ;
     RECT  20.401 10.224 20.437 11.688 ;
     RECT  19.397 13.2 20.437 17.976 ;
     RECT  20.437 10.032 20.473 11.688 ;
     RECT  20.437 13.104 20.473 18.216 ;
     RECT  20.473 13.008 20.509 18.216 ;
     RECT  20.005 20.208 20.545 38.28 ;
     RECT  20.509 13.008 20.581 18.888 ;
     RECT  20.581 13.008 21.301 18.984 ;
     RECT  20.545 20.112 21.301 38.28 ;
     RECT  20.473 9.936 21.564 11.784 ;
     RECT  21.301 13.008 21.564 38.28 ;
    LAYER M5 ;
     RECT  2.4 2.137 2.52 2.151 ;
     RECT  5.1 2.137 5.22 2.151 ;
     RECT  7.8 2.137 7.92 2.151 ;
     RECT  10.5 2.137 10.62 2.151 ;
     RECT  13.2 2.137 13.32 2.151 ;
     RECT  15.9 2.137 16.02 2.151 ;
     RECT  18.6 2.137 18.72 2.151 ;
     RECT  18.6 2.151 18.912 11.269 ;
     RECT  15.9 2.151 16.212 11.941 ;
     RECT  18.6 11.269 19.08 13.477 ;
     RECT  15.9 11.941 16.536 15.443 ;
     RECT  18.6 13.477 20.04 16.357 ;
     RECT  18.6 16.357 20.232 16.741 ;
     RECT  10.5 2.151 10.812 18.085 ;
     RECT  15.9 15.443 16.488 18.179 ;
     RECT  9.936 18.085 10.812 18.275 ;
     RECT  5.1 2.151 5.412 18.325 ;
     RECT  7.8 2.151 8.112 18.421 ;
     RECT  4.992 18.325 5.412 18.467 ;
     RECT  0.192 18.421 0.216 18.661 ;
     RECT  0.192 18.661 0.312 19.381 ;
     RECT  0.144 19.381 0.312 19.571 ;
     RECT  18.6 16.741 20.328 19.813 ;
     RECT  18.48 19.813 20.328 20.821 ;
     RECT  17.856 20.821 20.328 21.059 ;
     RECT  10.32 18.275 10.812 21.155 ;
     RECT  0.288 19.571 0.312 21.395 ;
     RECT  5.1 18.467 5.412 21.781 ;
     RECT  4.416 21.781 5.412 22.019 ;
     RECT  0.192 22.357 0.216 22.547 ;
     RECT  5.1 22.019 5.412 22.741 ;
     RECT  5.1 22.741 5.64 24.037 ;
     RECT  6.864 18.421 8.112 24.037 ;
     RECT  5.1 24.037 8.112 24.083 ;
     RECT  5.1 24.083 5.976 24.181 ;
     RECT  0.144 24.181 0.168 24.467 ;
     RECT  4.56 24.181 5.976 24.467 ;
     RECT  7.056 24.083 8.112 24.899 ;
     RECT  7.2 24.899 8.112 25.235 ;
     RECT  5.1 24.467 5.976 26.197 ;
     RECT  7.8 25.235 8.112 26.197 ;
     RECT  5.1 26.197 8.112 26.819 ;
     RECT  5.1 26.819 5.976 27.301 ;
     RECT  18.6 21.059 20.328 27.491 ;
     RECT  2.4 2.151 2.712 27.493 ;
     RECT  2.304 27.493 2.712 27.683 ;
     RECT  18.6 27.491 20.04 28.405 ;
     RECT  4.8 27.301 5.976 28.453 ;
     RECT  18.432 28.405 20.04 28.645 ;
     RECT  7.8 26.819 8.112 28.789 ;
     RECT  18.336 28.645 20.04 29.075 ;
     RECT  4.56 28.453 5.976 29.267 ;
     RECT  7.008 28.789 8.112 29.795 ;
     RECT  4.56 29.267 5.412 30.275 ;
     RECT  18.6 29.075 20.04 30.275 ;
     RECT  18.6 30.275 19.992 30.277 ;
     RECT  18.432 30.277 19.992 30.611 ;
     RECT  18.432 30.611 19.416 30.803 ;
     RECT  18.48 30.803 19.416 30.947 ;
     RECT  21.408 30.853 21.432 31.043 ;
     RECT  18.48 30.947 19.032 33.157 ;
     RECT  18.384 33.157 19.032 34.067 ;
     RECT  18.48 34.067 19.032 34.259 ;
     RECT  18.6 34.259 19.032 35.459 ;
     RECT  2.4 27.683 2.712 51.849 ;
     RECT  5.1 30.275 5.412 51.849 ;
     RECT  7.8 29.795 8.112 51.849 ;
     RECT  10.5 21.155 10.812 51.849 ;
     RECT  13.2 2.151 13.512 51.849 ;
     RECT  15.9 18.179 16.212 51.849 ;
     RECT  18.6 35.459 18.912 51.849 ;
     RECT  2.4 51.849 2.52 51.863 ;
     RECT  5.1 51.849 5.22 51.863 ;
     RECT  7.8 51.849 7.92 51.863 ;
     RECT  10.5 51.849 10.62 51.863 ;
     RECT  13.2 51.849 13.32 51.863 ;
     RECT  15.9 51.849 16.02 51.863 ;
     RECT  18.6 51.849 18.72 51.863 ;
  END
END hbfd_lh_136_WE_f2
END LIBRARY
